VERSION 5.8 ;
BUSBITCHARS "[]" ;
DIVIDERCHAR "/" ;
UNITS
    DATABASE MICRONS 1000 ;
END UNITS

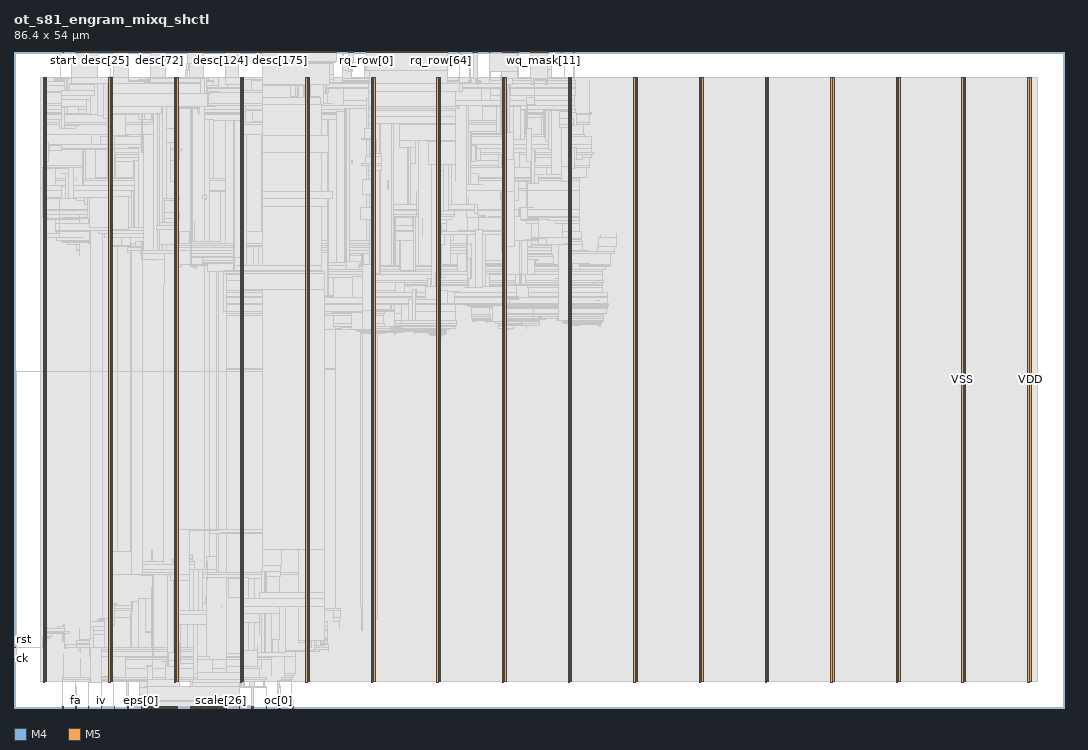
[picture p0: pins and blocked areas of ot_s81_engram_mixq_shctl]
MACRO ot_s81_engram_mixq_shctl
  FOREIGN ot_s81_engram_mixq_shctl 0 0 ;
  CLASS BLOCK ;
  SIZE 86.4 BY 54 ;
  PIN ck
    DIRECTION INPUT ;
    USE SIGNAL ;
    PORT
      LAYER M4 ;
        RECT  0 4.032 0.084 4.056 ;
    END
  END ck
  PIN copy[0]
    DIRECTION OUTPUT ;
    USE SIGNAL ;
    PORT
      LAYER M5 ;
        RECT  9.312 0 9.336 0.084 ;
    END
  END copy[0]
  PIN copy[1]
    DIRECTION OUTPUT ;
    USE SIGNAL ;
    PORT
      LAYER M5 ;
        RECT  9.408 0 9.432 0.084 ;
    END
  END copy[1]
  PIN desc[0]
    DIRECTION INPUT ;
    USE SIGNAL ;
    PORT
      LAYER M5 ;
        RECT  5.088 53.916 5.112 54 ;
    END
  END desc[0]
  PIN desc[100]
    DIRECTION INPUT ;
    USE SIGNAL ;
    PORT
      LAYER M5 ;
        RECT  14.688 53.916 14.712 54 ;
    END
  END desc[100]
  PIN desc[101]
    DIRECTION INPUT ;
    USE SIGNAL ;
    PORT
      LAYER M5 ;
        RECT  14.784 53.916 14.808 54 ;
    END
  END desc[101]
  PIN desc[102]
    DIRECTION INPUT ;
    USE SIGNAL ;
    PORT
      LAYER M5 ;
        RECT  14.88 53.916 14.904 54 ;
    END
  END desc[102]
  PIN desc[103]
    DIRECTION INPUT ;
    USE SIGNAL ;
    PORT
      LAYER M5 ;
        RECT  14.976 53.916 15 54 ;
    END
  END desc[103]
  PIN desc[104]
    DIRECTION INPUT ;
    USE SIGNAL ;
    PORT
      LAYER M5 ;
        RECT  15.072 53.916 15.096 54 ;
    END
  END desc[104]
  PIN desc[105]
    DIRECTION INPUT ;
    USE SIGNAL ;
    PORT
      LAYER M5 ;
        RECT  15.168 53.916 15.192 54 ;
    END
  END desc[105]
  PIN desc[106]
    DIRECTION INPUT ;
    USE SIGNAL ;
    PORT
      LAYER M5 ;
        RECT  15.264 53.916 15.288 54 ;
    END
  END desc[106]
  PIN desc[107]
    DIRECTION INPUT ;
    USE SIGNAL ;
    PORT
      LAYER M5 ;
        RECT  15.36 53.916 15.384 54 ;
    END
  END desc[107]
  PIN desc[108]
    DIRECTION INPUT ;
    USE SIGNAL ;
    PORT
      LAYER M5 ;
        RECT  15.456 53.916 15.48 54 ;
    END
  END desc[108]
  PIN desc[109]
    DIRECTION INPUT ;
    USE SIGNAL ;
    PORT
      LAYER M5 ;
        RECT  15.552 53.916 15.576 54 ;
    END
  END desc[109]
  PIN desc[10]
    DIRECTION INPUT ;
    USE SIGNAL ;
    PORT
      LAYER M5 ;
        RECT  6.048 53.916 6.072 54 ;
    END
  END desc[10]
  PIN desc[110]
    DIRECTION INPUT ;
    USE SIGNAL ;
    PORT
      LAYER M5 ;
        RECT  15.648 53.916 15.672 54 ;
    END
  END desc[110]
  PIN desc[111]
    DIRECTION INPUT ;
    USE SIGNAL ;
    PORT
      LAYER M5 ;
        RECT  15.744 53.916 15.768 54 ;
    END
  END desc[111]
  PIN desc[112]
    DIRECTION INPUT ;
    USE SIGNAL ;
    PORT
      LAYER M5 ;
        RECT  15.84 53.916 15.864 54 ;
    END
  END desc[112]
  PIN desc[113]
    DIRECTION INPUT ;
    USE SIGNAL ;
    PORT
      LAYER M5 ;
        RECT  15.936 53.916 15.96 54 ;
    END
  END desc[113]
  PIN desc[114]
    DIRECTION INPUT ;
    USE SIGNAL ;
    PORT
      LAYER M5 ;
        RECT  16.032 53.916 16.056 54 ;
    END
  END desc[114]
  PIN desc[115]
    DIRECTION INPUT ;
    USE SIGNAL ;
    PORT
      LAYER M5 ;
        RECT  16.128 53.916 16.152 54 ;
    END
  END desc[115]
  PIN desc[116]
    DIRECTION INPUT ;
    USE SIGNAL ;
    PORT
      LAYER M5 ;
        RECT  16.224 53.916 16.248 54 ;
    END
  END desc[116]
  PIN desc[117]
    DIRECTION INPUT ;
    USE SIGNAL ;
    PORT
      LAYER M5 ;
        RECT  16.32 53.916 16.344 54 ;
    END
  END desc[117]
  PIN desc[118]
    DIRECTION INPUT ;
    USE SIGNAL ;
    PORT
      LAYER M5 ;
        RECT  16.416 53.916 16.44 54 ;
    END
  END desc[118]
  PIN desc[119]
    DIRECTION INPUT ;
    USE SIGNAL ;
    PORT
      LAYER M5 ;
        RECT  16.512 53.916 16.536 54 ;
    END
  END desc[119]
  PIN desc[11]
    DIRECTION INPUT ;
    USE SIGNAL ;
    PORT
      LAYER M5 ;
        RECT  6.144 53.916 6.168 54 ;
    END
  END desc[11]
  PIN desc[120]
    DIRECTION INPUT ;
    USE SIGNAL ;
    PORT
      LAYER M5 ;
        RECT  16.608 53.916 16.632 54 ;
    END
  END desc[120]
  PIN desc[121]
    DIRECTION INPUT ;
    USE SIGNAL ;
    PORT
      LAYER M5 ;
        RECT  16.704 53.916 16.728 54 ;
    END
  END desc[121]
  PIN desc[122]
    DIRECTION INPUT ;
    USE SIGNAL ;
    PORT
      LAYER M5 ;
        RECT  16.8 53.916 16.824 54 ;
    END
  END desc[122]
  PIN desc[123]
    DIRECTION INPUT ;
    USE SIGNAL ;
    PORT
      LAYER M5 ;
        RECT  16.896 53.916 16.92 54 ;
    END
  END desc[123]
  PIN desc[124]
    DIRECTION INPUT ;
    USE SIGNAL ;
    PORT
      LAYER M5 ;
        RECT  16.992 53.916 17.016 54 ;
    END
  END desc[124]
  PIN desc[125]
    DIRECTION INPUT ;
    USE SIGNAL ;
    PORT
      LAYER M5 ;
        RECT  17.088 53.916 17.112 54 ;
    END
  END desc[125]
  PIN desc[126]
    DIRECTION INPUT ;
    USE SIGNAL ;
    PORT
      LAYER M5 ;
        RECT  17.184 53.916 17.208 54 ;
    END
  END desc[126]
  PIN desc[127]
    DIRECTION INPUT ;
    USE SIGNAL ;
    PORT
      LAYER M5 ;
        RECT  17.28 53.916 17.304 54 ;
    END
  END desc[127]
  PIN desc[128]
    DIRECTION INPUT ;
    USE SIGNAL ;
    PORT
      LAYER M5 ;
        RECT  17.376 53.916 17.4 54 ;
    END
  END desc[128]
  PIN desc[129]
    DIRECTION INPUT ;
    USE SIGNAL ;
    PORT
      LAYER M5 ;
        RECT  17.472 53.916 17.496 54 ;
    END
  END desc[129]
  PIN desc[12]
    DIRECTION INPUT ;
    USE SIGNAL ;
    PORT
      LAYER M5 ;
        RECT  6.24 53.916 6.264 54 ;
    END
  END desc[12]
  PIN desc[130]
    DIRECTION INPUT ;
    USE SIGNAL ;
    PORT
      LAYER M5 ;
        RECT  17.568 53.916 17.592 54 ;
    END
  END desc[130]
  PIN desc[131]
    DIRECTION INPUT ;
    USE SIGNAL ;
    PORT
      LAYER M5 ;
        RECT  17.664 53.916 17.688 54 ;
    END
  END desc[131]
  PIN desc[132]
    DIRECTION INPUT ;
    USE SIGNAL ;
    PORT
      LAYER M5 ;
        RECT  17.76 53.916 17.784 54 ;
    END
  END desc[132]
  PIN desc[133]
    DIRECTION INPUT ;
    USE SIGNAL ;
    PORT
      LAYER M5 ;
        RECT  17.856 53.916 17.88 54 ;
    END
  END desc[133]
  PIN desc[134]
    DIRECTION INPUT ;
    USE SIGNAL ;
    PORT
      LAYER M5 ;
        RECT  17.952 53.916 17.976 54 ;
    END
  END desc[134]
  PIN desc[135]
    DIRECTION INPUT ;
    USE SIGNAL ;
    PORT
      LAYER M5 ;
        RECT  18.048 53.916 18.072 54 ;
    END
  END desc[135]
  PIN desc[136]
    DIRECTION INPUT ;
    USE SIGNAL ;
    PORT
      LAYER M5 ;
        RECT  18.144 53.916 18.168 54 ;
    END
  END desc[136]
  PIN desc[137]
    DIRECTION INPUT ;
    USE SIGNAL ;
    PORT
      LAYER M5 ;
        RECT  18.24 53.916 18.264 54 ;
    END
  END desc[137]
  PIN desc[138]
    DIRECTION INPUT ;
    USE SIGNAL ;
    PORT
      LAYER M5 ;
        RECT  18.336 53.916 18.36 54 ;
    END
  END desc[138]
  PIN desc[139]
    DIRECTION INPUT ;
    USE SIGNAL ;
    PORT
      LAYER M5 ;
        RECT  18.432 53.916 18.456 54 ;
    END
  END desc[139]
  PIN desc[13]
    DIRECTION INPUT ;
    USE SIGNAL ;
    PORT
      LAYER M5 ;
        RECT  6.336 53.916 6.36 54 ;
    END
  END desc[13]
  PIN desc[140]
    DIRECTION INPUT ;
    USE SIGNAL ;
    PORT
      LAYER M5 ;
        RECT  18.528 53.916 18.552 54 ;
    END
  END desc[140]
  PIN desc[141]
    DIRECTION INPUT ;
    USE SIGNAL ;
    PORT
      LAYER M5 ;
        RECT  18.624 53.916 18.648 54 ;
    END
  END desc[141]
  PIN desc[142]
    DIRECTION INPUT ;
    USE SIGNAL ;
    PORT
      LAYER M5 ;
        RECT  18.72 53.916 18.744 54 ;
    END
  END desc[142]
  PIN desc[143]
    DIRECTION INPUT ;
    USE SIGNAL ;
    PORT
      LAYER M5 ;
        RECT  18.816 53.916 18.84 54 ;
    END
  END desc[143]
  PIN desc[144]
    DIRECTION INPUT ;
    USE SIGNAL ;
    PORT
      LAYER M5 ;
        RECT  18.912 53.916 18.936 54 ;
    END
  END desc[144]
  PIN desc[145]
    DIRECTION INPUT ;
    USE SIGNAL ;
    PORT
      LAYER M5 ;
        RECT  19.008 53.916 19.032 54 ;
    END
  END desc[145]
  PIN desc[146]
    DIRECTION INPUT ;
    USE SIGNAL ;
    PORT
      LAYER M5 ;
        RECT  19.104 53.916 19.128 54 ;
    END
  END desc[146]
  PIN desc[147]
    DIRECTION INPUT ;
    USE SIGNAL ;
    PORT
      LAYER M5 ;
        RECT  19.2 53.916 19.224 54 ;
    END
  END desc[147]
  PIN desc[148]
    DIRECTION INPUT ;
    USE SIGNAL ;
    PORT
      LAYER M5 ;
        RECT  19.296 53.916 19.32 54 ;
    END
  END desc[148]
  PIN desc[149]
    DIRECTION INPUT ;
    USE SIGNAL ;
    PORT
      LAYER M5 ;
        RECT  19.392 53.916 19.416 54 ;
    END
  END desc[149]
  PIN desc[14]
    DIRECTION INPUT ;
    USE SIGNAL ;
    PORT
      LAYER M5 ;
        RECT  6.432 53.916 6.456 54 ;
    END
  END desc[14]
  PIN desc[150]
    DIRECTION INPUT ;
    USE SIGNAL ;
    PORT
      LAYER M5 ;
        RECT  19.488 53.916 19.512 54 ;
    END
  END desc[150]
  PIN desc[151]
    DIRECTION INPUT ;
    USE SIGNAL ;
    PORT
      LAYER M5 ;
        RECT  19.584 53.916 19.608 54 ;
    END
  END desc[151]
  PIN desc[152]
    DIRECTION INPUT ;
    USE SIGNAL ;
    PORT
      LAYER M5 ;
        RECT  19.68 53.916 19.704 54 ;
    END
  END desc[152]
  PIN desc[153]
    DIRECTION INPUT ;
    USE SIGNAL ;
    PORT
      LAYER M5 ;
        RECT  19.776 53.916 19.8 54 ;
    END
  END desc[153]
  PIN desc[154]
    DIRECTION INPUT ;
    USE SIGNAL ;
    PORT
      LAYER M5 ;
        RECT  19.872 53.916 19.896 54 ;
    END
  END desc[154]
  PIN desc[155]
    DIRECTION INPUT ;
    USE SIGNAL ;
    PORT
      LAYER M5 ;
        RECT  19.968 53.916 19.992 54 ;
    END
  END desc[155]
  PIN desc[156]
    DIRECTION INPUT ;
    USE SIGNAL ;
    PORT
      LAYER M5 ;
        RECT  20.064 53.916 20.088 54 ;
    END
  END desc[156]
  PIN desc[157]
    DIRECTION INPUT ;
    USE SIGNAL ;
    PORT
      LAYER M5 ;
        RECT  20.16 53.916 20.184 54 ;
    END
  END desc[157]
  PIN desc[158]
    DIRECTION INPUT ;
    USE SIGNAL ;
    PORT
      LAYER M5 ;
        RECT  20.256 53.916 20.28 54 ;
    END
  END desc[158]
  PIN desc[159]
    DIRECTION INPUT ;
    USE SIGNAL ;
    PORT
      LAYER M5 ;
        RECT  20.352 53.916 20.376 54 ;
    END
  END desc[159]
  PIN desc[15]
    DIRECTION INPUT ;
    USE SIGNAL ;
    PORT
      LAYER M5 ;
        RECT  6.528 53.916 6.552 54 ;
    END
  END desc[15]
  PIN desc[160]
    DIRECTION INPUT ;
    USE SIGNAL ;
    PORT
      LAYER M5 ;
        RECT  20.448 53.916 20.472 54 ;
    END
  END desc[160]
  PIN desc[161]
    DIRECTION INPUT ;
    USE SIGNAL ;
    PORT
      LAYER M5 ;
        RECT  20.544 53.916 20.568 54 ;
    END
  END desc[161]
  PIN desc[162]
    DIRECTION INPUT ;
    USE SIGNAL ;
    PORT
      LAYER M5 ;
        RECT  20.64 53.916 20.664 54 ;
    END
  END desc[162]
  PIN desc[163]
    DIRECTION INPUT ;
    USE SIGNAL ;
    PORT
      LAYER M5 ;
        RECT  20.736 53.916 20.76 54 ;
    END
  END desc[163]
  PIN desc[164]
    DIRECTION INPUT ;
    USE SIGNAL ;
    PORT
      LAYER M5 ;
        RECT  20.832 53.916 20.856 54 ;
    END
  END desc[164]
  PIN desc[165]
    DIRECTION INPUT ;
    USE SIGNAL ;
    PORT
      LAYER M5 ;
        RECT  20.928 53.916 20.952 54 ;
    END
  END desc[165]
  PIN desc[166]
    DIRECTION INPUT ;
    USE SIGNAL ;
    PORT
      LAYER M5 ;
        RECT  21.024 53.916 21.048 54 ;
    END
  END desc[166]
  PIN desc[167]
    DIRECTION INPUT ;
    USE SIGNAL ;
    PORT
      LAYER M5 ;
        RECT  21.12 53.916 21.144 54 ;
    END
  END desc[167]
  PIN desc[168]
    DIRECTION INPUT ;
    USE SIGNAL ;
    PORT
      LAYER M5 ;
        RECT  21.216 53.916 21.24 54 ;
    END
  END desc[168]
  PIN desc[169]
    DIRECTION INPUT ;
    USE SIGNAL ;
    PORT
      LAYER M5 ;
        RECT  21.312 53.916 21.336 54 ;
    END
  END desc[169]
  PIN desc[16]
    DIRECTION INPUT ;
    USE SIGNAL ;
    PORT
      LAYER M5 ;
        RECT  6.624 53.916 6.648 54 ;
    END
  END desc[16]
  PIN desc[170]
    DIRECTION INPUT ;
    USE SIGNAL ;
    PORT
      LAYER M5 ;
        RECT  21.408 53.916 21.432 54 ;
    END
  END desc[170]
  PIN desc[171]
    DIRECTION INPUT ;
    USE SIGNAL ;
    PORT
      LAYER M5 ;
        RECT  21.504 53.916 21.528 54 ;
    END
  END desc[171]
  PIN desc[172]
    DIRECTION INPUT ;
    USE SIGNAL ;
    PORT
      LAYER M5 ;
        RECT  21.6 53.916 21.624 54 ;
    END
  END desc[172]
  PIN desc[173]
    DIRECTION INPUT ;
    USE SIGNAL ;
    PORT
      LAYER M5 ;
        RECT  21.696 53.916 21.72 54 ;
    END
  END desc[173]
  PIN desc[174]
    DIRECTION INPUT ;
    USE SIGNAL ;
    PORT
      LAYER M5 ;
        RECT  21.792 53.916 21.816 54 ;
    END
  END desc[174]
  PIN desc[175]
    DIRECTION INPUT ;
    USE SIGNAL ;
    PORT
      LAYER M5 ;
        RECT  21.888 53.916 21.912 54 ;
    END
  END desc[175]
  PIN desc[176]
    DIRECTION INPUT ;
    USE SIGNAL ;
    PORT
      LAYER M5 ;
        RECT  21.984 53.916 22.008 54 ;
    END
  END desc[176]
  PIN desc[177]
    DIRECTION INPUT ;
    USE SIGNAL ;
    PORT
      LAYER M5 ;
        RECT  22.08 53.916 22.104 54 ;
    END
  END desc[177]
  PIN desc[178]
    DIRECTION INPUT ;
    USE SIGNAL ;
    PORT
      LAYER M5 ;
        RECT  22.176 53.916 22.2 54 ;
    END
  END desc[178]
  PIN desc[179]
    DIRECTION INPUT ;
    USE SIGNAL ;
    PORT
      LAYER M5 ;
        RECT  22.272 53.916 22.296 54 ;
    END
  END desc[179]
  PIN desc[17]
    DIRECTION INPUT ;
    USE SIGNAL ;
    PORT
      LAYER M5 ;
        RECT  6.72 53.916 6.744 54 ;
    END
  END desc[17]
  PIN desc[180]
    DIRECTION INPUT ;
    USE SIGNAL ;
    PORT
      LAYER M5 ;
        RECT  22.368 53.916 22.392 54 ;
    END
  END desc[180]
  PIN desc[181]
    DIRECTION INPUT ;
    USE SIGNAL ;
    PORT
      LAYER M5 ;
        RECT  22.464 53.916 22.488 54 ;
    END
  END desc[181]
  PIN desc[182]
    DIRECTION INPUT ;
    USE SIGNAL ;
    PORT
      LAYER M5 ;
        RECT  22.56 53.916 22.584 54 ;
    END
  END desc[182]
  PIN desc[183]
    DIRECTION INPUT ;
    USE SIGNAL ;
    PORT
      LAYER M5 ;
        RECT  22.656 53.916 22.68 54 ;
    END
  END desc[183]
  PIN desc[184]
    DIRECTION INPUT ;
    USE SIGNAL ;
    PORT
      LAYER M5 ;
        RECT  22.752 53.916 22.776 54 ;
    END
  END desc[184]
  PIN desc[185]
    DIRECTION INPUT ;
    USE SIGNAL ;
    PORT
      LAYER M5 ;
        RECT  22.848 53.916 22.872 54 ;
    END
  END desc[185]
  PIN desc[186]
    DIRECTION INPUT ;
    USE SIGNAL ;
    PORT
      LAYER M5 ;
        RECT  22.944 53.916 22.968 54 ;
    END
  END desc[186]
  PIN desc[187]
    DIRECTION INPUT ;
    USE SIGNAL ;
    PORT
      LAYER M5 ;
        RECT  23.04 53.916 23.064 54 ;
    END
  END desc[187]
  PIN desc[188]
    DIRECTION INPUT ;
    USE SIGNAL ;
    PORT
      LAYER M5 ;
        RECT  23.136 53.916 23.16 54 ;
    END
  END desc[188]
  PIN desc[189]
    DIRECTION INPUT ;
    USE SIGNAL ;
    PORT
      LAYER M5 ;
        RECT  23.232 53.916 23.256 54 ;
    END
  END desc[189]
  PIN desc[18]
    DIRECTION INPUT ;
    USE SIGNAL ;
    PORT
      LAYER M5 ;
        RECT  6.816 53.916 6.84 54 ;
    END
  END desc[18]
  PIN desc[190]
    DIRECTION INPUT ;
    USE SIGNAL ;
    PORT
      LAYER M5 ;
        RECT  23.328 53.916 23.352 54 ;
    END
  END desc[190]
  PIN desc[191]
    DIRECTION INPUT ;
    USE SIGNAL ;
    PORT
      LAYER M5 ;
        RECT  23.424 53.916 23.448 54 ;
    END
  END desc[191]
  PIN desc[192]
    DIRECTION INPUT ;
    USE SIGNAL ;
    PORT
      LAYER M5 ;
        RECT  23.52 53.916 23.544 54 ;
    END
  END desc[192]
  PIN desc[193]
    DIRECTION INPUT ;
    USE SIGNAL ;
    PORT
      LAYER M5 ;
        RECT  23.616 53.916 23.64 54 ;
    END
  END desc[193]
  PIN desc[194]
    DIRECTION INPUT ;
    USE SIGNAL ;
    PORT
      LAYER M5 ;
        RECT  23.712 53.916 23.736 54 ;
    END
  END desc[194]
  PIN desc[195]
    DIRECTION INPUT ;
    USE SIGNAL ;
    PORT
      LAYER M5 ;
        RECT  23.808 53.916 23.832 54 ;
    END
  END desc[195]
  PIN desc[196]
    DIRECTION INPUT ;
    USE SIGNAL ;
    PORT
      LAYER M5 ;
        RECT  23.904 53.916 23.928 54 ;
    END
  END desc[196]
  PIN desc[197]
    DIRECTION INPUT ;
    USE SIGNAL ;
    PORT
      LAYER M5 ;
        RECT  24 53.916 24.024 54 ;
    END
  END desc[197]
  PIN desc[198]
    DIRECTION INPUT ;
    USE SIGNAL ;
    PORT
      LAYER M5 ;
        RECT  24.096 53.916 24.12 54 ;
    END
  END desc[198]
  PIN desc[199]
    DIRECTION INPUT ;
    USE SIGNAL ;
    PORT
      LAYER M5 ;
        RECT  24.192 53.916 24.216 54 ;
    END
  END desc[199]
  PIN desc[19]
    DIRECTION INPUT ;
    USE SIGNAL ;
    PORT
      LAYER M5 ;
        RECT  6.912 53.916 6.936 54 ;
    END
  END desc[19]
  PIN desc[1]
    DIRECTION INPUT ;
    USE SIGNAL ;
    PORT
      LAYER M5 ;
        RECT  5.184 53.916 5.208 54 ;
    END
  END desc[1]
  PIN desc[200]
    DIRECTION INPUT ;
    USE SIGNAL ;
    PORT
      LAYER M5 ;
        RECT  24.288 53.916 24.312 54 ;
    END
  END desc[200]
  PIN desc[201]
    DIRECTION INPUT ;
    USE SIGNAL ;
    PORT
      LAYER M5 ;
        RECT  24.384 53.916 24.408 54 ;
    END
  END desc[201]
  PIN desc[202]
    DIRECTION INPUT ;
    USE SIGNAL ;
    PORT
      LAYER M5 ;
        RECT  24.48 53.916 24.504 54 ;
    END
  END desc[202]
  PIN desc[203]
    DIRECTION INPUT ;
    USE SIGNAL ;
    PORT
      LAYER M5 ;
        RECT  24.576 53.916 24.6 54 ;
    END
  END desc[203]
  PIN desc[204]
    DIRECTION INPUT ;
    USE SIGNAL ;
    PORT
      LAYER M5 ;
        RECT  24.672 53.916 24.696 54 ;
    END
  END desc[204]
  PIN desc[205]
    DIRECTION INPUT ;
    USE SIGNAL ;
    PORT
      LAYER M5 ;
        RECT  24.768 53.916 24.792 54 ;
    END
  END desc[205]
  PIN desc[206]
    DIRECTION INPUT ;
    USE SIGNAL ;
    PORT
      LAYER M5 ;
        RECT  24.864 53.916 24.888 54 ;
    END
  END desc[206]
  PIN desc[207]
    DIRECTION INPUT ;
    USE SIGNAL ;
    PORT
      LAYER M5 ;
        RECT  24.96 53.916 24.984 54 ;
    END
  END desc[207]
  PIN desc[208]
    DIRECTION INPUT ;
    USE SIGNAL ;
    PORT
      LAYER M5 ;
        RECT  25.056 53.916 25.08 54 ;
    END
  END desc[208]
  PIN desc[209]
    DIRECTION INPUT ;
    USE SIGNAL ;
    PORT
      LAYER M5 ;
        RECT  25.152 53.916 25.176 54 ;
    END
  END desc[209]
  PIN desc[20]
    DIRECTION INPUT ;
    USE SIGNAL ;
    PORT
      LAYER M5 ;
        RECT  7.008 53.916 7.032 54 ;
    END
  END desc[20]
  PIN desc[210]
    DIRECTION INPUT ;
    USE SIGNAL ;
    PORT
      LAYER M5 ;
        RECT  25.248 53.916 25.272 54 ;
    END
  END desc[210]
  PIN desc[211]
    DIRECTION INPUT ;
    USE SIGNAL ;
    PORT
      LAYER M5 ;
        RECT  25.344 53.916 25.368 54 ;
    END
  END desc[211]
  PIN desc[212]
    DIRECTION INPUT ;
    USE SIGNAL ;
    PORT
      LAYER M5 ;
        RECT  25.44 53.916 25.464 54 ;
    END
  END desc[212]
  PIN desc[213]
    DIRECTION INPUT ;
    USE SIGNAL ;
    PORT
      LAYER M5 ;
        RECT  25.536 53.916 25.56 54 ;
    END
  END desc[213]
  PIN desc[214]
    DIRECTION INPUT ;
    USE SIGNAL ;
    PORT
      LAYER M5 ;
        RECT  25.632 53.916 25.656 54 ;
    END
  END desc[214]
  PIN desc[215]
    DIRECTION INPUT ;
    USE SIGNAL ;
    PORT
      LAYER M5 ;
        RECT  25.728 53.916 25.752 54 ;
    END
  END desc[215]
  PIN desc[216]
    DIRECTION INPUT ;
    USE SIGNAL ;
    PORT
      LAYER M5 ;
        RECT  25.824 53.916 25.848 54 ;
    END
  END desc[216]
  PIN desc[217]
    DIRECTION INPUT ;
    USE SIGNAL ;
    PORT
      LAYER M5 ;
        RECT  25.92 53.916 25.944 54 ;
    END
  END desc[217]
  PIN desc[218]
    DIRECTION INPUT ;
    USE SIGNAL ;
    PORT
      LAYER M5 ;
        RECT  26.016 53.916 26.04 54 ;
    END
  END desc[218]
  PIN desc[219]
    DIRECTION INPUT ;
    USE SIGNAL ;
    PORT
      LAYER M5 ;
        RECT  26.112 53.916 26.136 54 ;
    END
  END desc[219]
  PIN desc[21]
    DIRECTION INPUT ;
    USE SIGNAL ;
    PORT
      LAYER M5 ;
        RECT  7.104 53.916 7.128 54 ;
    END
  END desc[21]
  PIN desc[220]
    DIRECTION INPUT ;
    USE SIGNAL ;
    PORT
      LAYER M5 ;
        RECT  26.208 53.916 26.232 54 ;
    END
  END desc[220]
  PIN desc[221]
    DIRECTION INPUT ;
    USE SIGNAL ;
    PORT
      LAYER M5 ;
        RECT  26.304 53.916 26.328 54 ;
    END
  END desc[221]
  PIN desc[222]
    DIRECTION INPUT ;
    USE SIGNAL ;
    PORT
      LAYER M5 ;
        RECT  26.4 53.916 26.424 54 ;
    END
  END desc[222]
  PIN desc[223]
    DIRECTION INPUT ;
    USE SIGNAL ;
    PORT
      LAYER M5 ;
        RECT  26.496 53.916 26.52 54 ;
    END
  END desc[223]
  PIN desc[22]
    DIRECTION INPUT ;
    USE SIGNAL ;
    PORT
      LAYER M5 ;
        RECT  7.2 53.916 7.224 54 ;
    END
  END desc[22]
  PIN desc[23]
    DIRECTION INPUT ;
    USE SIGNAL ;
    PORT
      LAYER M5 ;
        RECT  7.296 53.916 7.32 54 ;
    END
  END desc[23]
  PIN desc[24]
    DIRECTION INPUT ;
    USE SIGNAL ;
    PORT
      LAYER M5 ;
        RECT  7.392 53.916 7.416 54 ;
    END
  END desc[24]
  PIN desc[25]
    DIRECTION INPUT ;
    USE SIGNAL ;
    PORT
      LAYER M5 ;
        RECT  7.488 53.916 7.512 54 ;
    END
  END desc[25]
  PIN desc[26]
    DIRECTION INPUT ;
    USE SIGNAL ;
    PORT
      LAYER M5 ;
        RECT  7.584 53.916 7.608 54 ;
    END
  END desc[26]
  PIN desc[27]
    DIRECTION INPUT ;
    USE SIGNAL ;
    PORT
      LAYER M5 ;
        RECT  7.68 53.916 7.704 54 ;
    END
  END desc[27]
  PIN desc[28]
    DIRECTION INPUT ;
    USE SIGNAL ;
    PORT
      LAYER M5 ;
        RECT  7.776 53.916 7.8 54 ;
    END
  END desc[28]
  PIN desc[29]
    DIRECTION INPUT ;
    USE SIGNAL ;
    PORT
      LAYER M5 ;
        RECT  7.872 53.916 7.896 54 ;
    END
  END desc[29]
  PIN desc[2]
    DIRECTION INPUT ;
    USE SIGNAL ;
    PORT
      LAYER M5 ;
        RECT  5.28 53.916 5.304 54 ;
    END
  END desc[2]
  PIN desc[30]
    DIRECTION INPUT ;
    USE SIGNAL ;
    PORT
      LAYER M5 ;
        RECT  7.968 53.916 7.992 54 ;
    END
  END desc[30]
  PIN desc[31]
    DIRECTION INPUT ;
    USE SIGNAL ;
    PORT
      LAYER M5 ;
        RECT  8.064 53.916 8.088 54 ;
    END
  END desc[31]
  PIN desc[32]
    DIRECTION INPUT ;
    USE SIGNAL ;
    PORT
      LAYER M5 ;
        RECT  8.16 53.916 8.184 54 ;
    END
  END desc[32]
  PIN desc[33]
    DIRECTION INPUT ;
    USE SIGNAL ;
    PORT
      LAYER M5 ;
        RECT  8.256 53.916 8.28 54 ;
    END
  END desc[33]
  PIN desc[34]
    DIRECTION INPUT ;
    USE SIGNAL ;
    PORT
      LAYER M5 ;
        RECT  8.352 53.916 8.376 54 ;
    END
  END desc[34]
  PIN desc[35]
    DIRECTION INPUT ;
    USE SIGNAL ;
    PORT
      LAYER M5 ;
        RECT  8.448 53.916 8.472 54 ;
    END
  END desc[35]
  PIN desc[36]
    DIRECTION INPUT ;
    USE SIGNAL ;
    PORT
      LAYER M5 ;
        RECT  8.544 53.916 8.568 54 ;
    END
  END desc[36]
  PIN desc[37]
    DIRECTION INPUT ;
    USE SIGNAL ;
    PORT
      LAYER M5 ;
        RECT  8.64 53.916 8.664 54 ;
    END
  END desc[37]
  PIN desc[38]
    DIRECTION INPUT ;
    USE SIGNAL ;
    PORT
      LAYER M5 ;
        RECT  8.736 53.916 8.76 54 ;
    END
  END desc[38]
  PIN desc[39]
    DIRECTION INPUT ;
    USE SIGNAL ;
    PORT
      LAYER M5 ;
        RECT  8.832 53.916 8.856 54 ;
    END
  END desc[39]
  PIN desc[3]
    DIRECTION INPUT ;
    USE SIGNAL ;
    PORT
      LAYER M5 ;
        RECT  5.376 53.916 5.4 54 ;
    END
  END desc[3]
  PIN desc[40]
    DIRECTION INPUT ;
    USE SIGNAL ;
    PORT
      LAYER M5 ;
        RECT  8.928 53.916 8.952 54 ;
    END
  END desc[40]
  PIN desc[41]
    DIRECTION INPUT ;
    USE SIGNAL ;
    PORT
      LAYER M5 ;
        RECT  9.024 53.916 9.048 54 ;
    END
  END desc[41]
  PIN desc[42]
    DIRECTION INPUT ;
    USE SIGNAL ;
    PORT
      LAYER M5 ;
        RECT  9.12 53.916 9.144 54 ;
    END
  END desc[42]
  PIN desc[43]
    DIRECTION INPUT ;
    USE SIGNAL ;
    PORT
      LAYER M5 ;
        RECT  9.216 53.916 9.24 54 ;
    END
  END desc[43]
  PIN desc[44]
    DIRECTION INPUT ;
    USE SIGNAL ;
    PORT
      LAYER M5 ;
        RECT  9.312 53.916 9.336 54 ;
    END
  END desc[44]
  PIN desc[45]
    DIRECTION INPUT ;
    USE SIGNAL ;
    PORT
      LAYER M5 ;
        RECT  9.408 53.916 9.432 54 ;
    END
  END desc[45]
  PIN desc[46]
    DIRECTION INPUT ;
    USE SIGNAL ;
    PORT
      LAYER M5 ;
        RECT  9.504 53.916 9.528 54 ;
    END
  END desc[46]
  PIN desc[47]
    DIRECTION INPUT ;
    USE SIGNAL ;
    PORT
      LAYER M5 ;
        RECT  9.6 53.916 9.624 54 ;
    END
  END desc[47]
  PIN desc[48]
    DIRECTION INPUT ;
    USE SIGNAL ;
    PORT
      LAYER M5 ;
        RECT  9.696 53.916 9.72 54 ;
    END
  END desc[48]
  PIN desc[49]
    DIRECTION INPUT ;
    USE SIGNAL ;
    PORT
      LAYER M5 ;
        RECT  9.792 53.916 9.816 54 ;
    END
  END desc[49]
  PIN desc[4]
    DIRECTION INPUT ;
    USE SIGNAL ;
    PORT
      LAYER M5 ;
        RECT  5.472 53.916 5.496 54 ;
    END
  END desc[4]
  PIN desc[50]
    DIRECTION INPUT ;
    USE SIGNAL ;
    PORT
      LAYER M5 ;
        RECT  9.888 53.916 9.912 54 ;
    END
  END desc[50]
  PIN desc[51]
    DIRECTION INPUT ;
    USE SIGNAL ;
    PORT
      LAYER M5 ;
        RECT  9.984 53.916 10.008 54 ;
    END
  END desc[51]
  PIN desc[52]
    DIRECTION INPUT ;
    USE SIGNAL ;
    PORT
      LAYER M5 ;
        RECT  10.08 53.916 10.104 54 ;
    END
  END desc[52]
  PIN desc[53]
    DIRECTION INPUT ;
    USE SIGNAL ;
    PORT
      LAYER M5 ;
        RECT  10.176 53.916 10.2 54 ;
    END
  END desc[53]
  PIN desc[54]
    DIRECTION INPUT ;
    USE SIGNAL ;
    PORT
      LAYER M5 ;
        RECT  10.272 53.916 10.296 54 ;
    END
  END desc[54]
  PIN desc[55]
    DIRECTION INPUT ;
    USE SIGNAL ;
    PORT
      LAYER M5 ;
        RECT  10.368 53.916 10.392 54 ;
    END
  END desc[55]
  PIN desc[56]
    DIRECTION INPUT ;
    USE SIGNAL ;
    PORT
      LAYER M5 ;
        RECT  10.464 53.916 10.488 54 ;
    END
  END desc[56]
  PIN desc[57]
    DIRECTION INPUT ;
    USE SIGNAL ;
    PORT
      LAYER M5 ;
        RECT  10.56 53.916 10.584 54 ;
    END
  END desc[57]
  PIN desc[58]
    DIRECTION INPUT ;
    USE SIGNAL ;
    PORT
      LAYER M5 ;
        RECT  10.656 53.916 10.68 54 ;
    END
  END desc[58]
  PIN desc[59]
    DIRECTION INPUT ;
    USE SIGNAL ;
    PORT
      LAYER M5 ;
        RECT  10.752 53.916 10.776 54 ;
    END
  END desc[59]
  PIN desc[5]
    DIRECTION INPUT ;
    USE SIGNAL ;
    PORT
      LAYER M5 ;
        RECT  5.568 53.916 5.592 54 ;
    END
  END desc[5]
  PIN desc[60]
    DIRECTION INPUT ;
    USE SIGNAL ;
    PORT
      LAYER M5 ;
        RECT  10.848 53.916 10.872 54 ;
    END
  END desc[60]
  PIN desc[61]
    DIRECTION INPUT ;
    USE SIGNAL ;
    PORT
      LAYER M5 ;
        RECT  10.944 53.916 10.968 54 ;
    END
  END desc[61]
  PIN desc[62]
    DIRECTION INPUT ;
    USE SIGNAL ;
    PORT
      LAYER M5 ;
        RECT  11.04 53.916 11.064 54 ;
    END
  END desc[62]
  PIN desc[63]
    DIRECTION INPUT ;
    USE SIGNAL ;
    PORT
      LAYER M5 ;
        RECT  11.136 53.916 11.16 54 ;
    END
  END desc[63]
  PIN desc[64]
    DIRECTION INPUT ;
    USE SIGNAL ;
    PORT
      LAYER M5 ;
        RECT  11.232 53.916 11.256 54 ;
    END
  END desc[64]
  PIN desc[65]
    DIRECTION INPUT ;
    USE SIGNAL ;
    PORT
      LAYER M5 ;
        RECT  11.328 53.916 11.352 54 ;
    END
  END desc[65]
  PIN desc[66]
    DIRECTION INPUT ;
    USE SIGNAL ;
    PORT
      LAYER M5 ;
        RECT  11.424 53.916 11.448 54 ;
    END
  END desc[66]
  PIN desc[67]
    DIRECTION INPUT ;
    USE SIGNAL ;
    PORT
      LAYER M5 ;
        RECT  11.52 53.916 11.544 54 ;
    END
  END desc[67]
  PIN desc[68]
    DIRECTION INPUT ;
    USE SIGNAL ;
    PORT
      LAYER M5 ;
        RECT  11.616 53.916 11.64 54 ;
    END
  END desc[68]
  PIN desc[69]
    DIRECTION INPUT ;
    USE SIGNAL ;
    PORT
      LAYER M5 ;
        RECT  11.712 53.916 11.736 54 ;
    END
  END desc[69]
  PIN desc[6]
    DIRECTION INPUT ;
    USE SIGNAL ;
    PORT
      LAYER M5 ;
        RECT  5.664 53.916 5.688 54 ;
    END
  END desc[6]
  PIN desc[70]
    DIRECTION INPUT ;
    USE SIGNAL ;
    PORT
      LAYER M5 ;
        RECT  11.808 53.916 11.832 54 ;
    END
  END desc[70]
  PIN desc[71]
    DIRECTION INPUT ;
    USE SIGNAL ;
    PORT
      LAYER M5 ;
        RECT  11.904 53.916 11.928 54 ;
    END
  END desc[71]
  PIN desc[72]
    DIRECTION INPUT ;
    USE SIGNAL ;
    PORT
      LAYER M5 ;
        RECT  12 53.916 12.024 54 ;
    END
  END desc[72]
  PIN desc[73]
    DIRECTION INPUT ;
    USE SIGNAL ;
    PORT
      LAYER M5 ;
        RECT  12.096 53.916 12.12 54 ;
    END
  END desc[73]
  PIN desc[74]
    DIRECTION INPUT ;
    USE SIGNAL ;
    PORT
      LAYER M5 ;
        RECT  12.192 53.916 12.216 54 ;
    END
  END desc[74]
  PIN desc[75]
    DIRECTION INPUT ;
    USE SIGNAL ;
    PORT
      LAYER M5 ;
        RECT  12.288 53.916 12.312 54 ;
    END
  END desc[75]
  PIN desc[76]
    DIRECTION INPUT ;
    USE SIGNAL ;
    PORT
      LAYER M5 ;
        RECT  12.384 53.916 12.408 54 ;
    END
  END desc[76]
  PIN desc[77]
    DIRECTION INPUT ;
    USE SIGNAL ;
    PORT
      LAYER M5 ;
        RECT  12.48 53.916 12.504 54 ;
    END
  END desc[77]
  PIN desc[78]
    DIRECTION INPUT ;
    USE SIGNAL ;
    PORT
      LAYER M5 ;
        RECT  12.576 53.916 12.6 54 ;
    END
  END desc[78]
  PIN desc[79]
    DIRECTION INPUT ;
    USE SIGNAL ;
    PORT
      LAYER M5 ;
        RECT  12.672 53.916 12.696 54 ;
    END
  END desc[79]
  PIN desc[7]
    DIRECTION INPUT ;
    USE SIGNAL ;
    PORT
      LAYER M5 ;
        RECT  5.76 53.916 5.784 54 ;
    END
  END desc[7]
  PIN desc[80]
    DIRECTION INPUT ;
    USE SIGNAL ;
    PORT
      LAYER M5 ;
        RECT  12.768 53.916 12.792 54 ;
    END
  END desc[80]
  PIN desc[81]
    DIRECTION INPUT ;
    USE SIGNAL ;
    PORT
      LAYER M5 ;
        RECT  12.864 53.916 12.888 54 ;
    END
  END desc[81]
  PIN desc[82]
    DIRECTION INPUT ;
    USE SIGNAL ;
    PORT
      LAYER M5 ;
        RECT  12.96 53.916 12.984 54 ;
    END
  END desc[82]
  PIN desc[83]
    DIRECTION INPUT ;
    USE SIGNAL ;
    PORT
      LAYER M5 ;
        RECT  13.056 53.916 13.08 54 ;
    END
  END desc[83]
  PIN desc[84]
    DIRECTION INPUT ;
    USE SIGNAL ;
    PORT
      LAYER M5 ;
        RECT  13.152 53.916 13.176 54 ;
    END
  END desc[84]
  PIN desc[85]
    DIRECTION INPUT ;
    USE SIGNAL ;
    PORT
      LAYER M5 ;
        RECT  13.248 53.916 13.272 54 ;
    END
  END desc[85]
  PIN desc[86]
    DIRECTION INPUT ;
    USE SIGNAL ;
    PORT
      LAYER M5 ;
        RECT  13.344 53.916 13.368 54 ;
    END
  END desc[86]
  PIN desc[87]
    DIRECTION INPUT ;
    USE SIGNAL ;
    PORT
      LAYER M5 ;
        RECT  13.44 53.916 13.464 54 ;
    END
  END desc[87]
  PIN desc[88]
    DIRECTION INPUT ;
    USE SIGNAL ;
    PORT
      LAYER M5 ;
        RECT  13.536 53.916 13.56 54 ;
    END
  END desc[88]
  PIN desc[89]
    DIRECTION INPUT ;
    USE SIGNAL ;
    PORT
      LAYER M5 ;
        RECT  13.632 53.916 13.656 54 ;
    END
  END desc[89]
  PIN desc[8]
    DIRECTION INPUT ;
    USE SIGNAL ;
    PORT
      LAYER M5 ;
        RECT  5.856 53.916 5.88 54 ;
    END
  END desc[8]
  PIN desc[90]
    DIRECTION INPUT ;
    USE SIGNAL ;
    PORT
      LAYER M5 ;
        RECT  13.728 53.916 13.752 54 ;
    END
  END desc[90]
  PIN desc[91]
    DIRECTION INPUT ;
    USE SIGNAL ;
    PORT
      LAYER M5 ;
        RECT  13.824 53.916 13.848 54 ;
    END
  END desc[91]
  PIN desc[92]
    DIRECTION INPUT ;
    USE SIGNAL ;
    PORT
      LAYER M5 ;
        RECT  13.92 53.916 13.944 54 ;
    END
  END desc[92]
  PIN desc[93]
    DIRECTION INPUT ;
    USE SIGNAL ;
    PORT
      LAYER M5 ;
        RECT  14.016 53.916 14.04 54 ;
    END
  END desc[93]
  PIN desc[94]
    DIRECTION INPUT ;
    USE SIGNAL ;
    PORT
      LAYER M5 ;
        RECT  14.112 53.916 14.136 54 ;
    END
  END desc[94]
  PIN desc[95]
    DIRECTION INPUT ;
    USE SIGNAL ;
    PORT
      LAYER M5 ;
        RECT  14.208 53.916 14.232 54 ;
    END
  END desc[95]
  PIN desc[96]
    DIRECTION INPUT ;
    USE SIGNAL ;
    PORT
      LAYER M5 ;
        RECT  14.304 53.916 14.328 54 ;
    END
  END desc[96]
  PIN desc[97]
    DIRECTION INPUT ;
    USE SIGNAL ;
    PORT
      LAYER M5 ;
        RECT  14.4 53.916 14.424 54 ;
    END
  END desc[97]
  PIN desc[98]
    DIRECTION INPUT ;
    USE SIGNAL ;
    PORT
      LAYER M5 ;
        RECT  14.496 53.916 14.52 54 ;
    END
  END desc[98]
  PIN desc[99]
    DIRECTION INPUT ;
    USE SIGNAL ;
    PORT
      LAYER M5 ;
        RECT  14.592 53.916 14.616 54 ;
    END
  END desc[99]
  PIN desc[9]
    DIRECTION INPUT ;
    USE SIGNAL ;
    PORT
      LAYER M5 ;
        RECT  5.952 53.916 5.976 54 ;
    END
  END desc[9]
  PIN done
    DIRECTION OUTPUT ;
    USE SIGNAL ;
    PORT
      LAYER M5 ;
        RECT  45.024 53.916 45.048 54 ;
    END
  END done
  PIN eps[0]
    DIRECTION OUTPUT ;
    USE SIGNAL ;
    PORT
      LAYER M5 ;
        RECT  10.464 0 10.488 0.084 ;
    END
  END eps[0]
  PIN eps[10]
    DIRECTION OUTPUT ;
    USE SIGNAL ;
    PORT
      LAYER M5 ;
        RECT  11.424 0 11.448 0.084 ;
    END
  END eps[10]
  PIN eps[11]
    DIRECTION OUTPUT ;
    USE SIGNAL ;
    PORT
      LAYER M5 ;
        RECT  11.52 0 11.544 0.084 ;
    END
  END eps[11]
  PIN eps[12]
    DIRECTION OUTPUT ;
    USE SIGNAL ;
    PORT
      LAYER M5 ;
        RECT  11.616 0 11.64 0.084 ;
    END
  END eps[12]
  PIN eps[13]
    DIRECTION OUTPUT ;
    USE SIGNAL ;
    PORT
      LAYER M5 ;
        RECT  11.712 0 11.736 0.084 ;
    END
  END eps[13]
  PIN eps[14]
    DIRECTION OUTPUT ;
    USE SIGNAL ;
    PORT
      LAYER M5 ;
        RECT  11.808 0 11.832 0.084 ;
    END
  END eps[14]
  PIN eps[15]
    DIRECTION OUTPUT ;
    USE SIGNAL ;
    PORT
      LAYER M5 ;
        RECT  11.904 0 11.928 0.084 ;
    END
  END eps[15]
  PIN eps[16]
    DIRECTION OUTPUT ;
    USE SIGNAL ;
    PORT
      LAYER M5 ;
        RECT  12 0 12.024 0.084 ;
    END
  END eps[16]
  PIN eps[17]
    DIRECTION OUTPUT ;
    USE SIGNAL ;
    PORT
      LAYER M5 ;
        RECT  12.096 0 12.12 0.084 ;
    END
  END eps[17]
  PIN eps[18]
    DIRECTION OUTPUT ;
    USE SIGNAL ;
    PORT
      LAYER M5 ;
        RECT  12.192 0 12.216 0.084 ;
    END
  END eps[18]
  PIN eps[19]
    DIRECTION OUTPUT ;
    USE SIGNAL ;
    PORT
      LAYER M5 ;
        RECT  12.288 0 12.312 0.084 ;
    END
  END eps[19]
  PIN eps[1]
    DIRECTION OUTPUT ;
    USE SIGNAL ;
    PORT
      LAYER M5 ;
        RECT  10.56 0 10.584 0.084 ;
    END
  END eps[1]
  PIN eps[20]
    DIRECTION OUTPUT ;
    USE SIGNAL ;
    PORT
      LAYER M5 ;
        RECT  12.384 0 12.408 0.084 ;
    END
  END eps[20]
  PIN eps[21]
    DIRECTION OUTPUT ;
    USE SIGNAL ;
    PORT
      LAYER M5 ;
        RECT  12.48 0 12.504 0.084 ;
    END
  END eps[21]
  PIN eps[22]
    DIRECTION OUTPUT ;
    USE SIGNAL ;
    PORT
      LAYER M5 ;
        RECT  12.576 0 12.6 0.084 ;
    END
  END eps[22]
  PIN eps[23]
    DIRECTION OUTPUT ;
    USE SIGNAL ;
    PORT
      LAYER M5 ;
        RECT  12.672 0 12.696 0.084 ;
    END
  END eps[23]
  PIN eps[24]
    DIRECTION OUTPUT ;
    USE SIGNAL ;
    PORT
      LAYER M5 ;
        RECT  12.768 0 12.792 0.084 ;
    END
  END eps[24]
  PIN eps[25]
    DIRECTION OUTPUT ;
    USE SIGNAL ;
    PORT
      LAYER M5 ;
        RECT  12.864 0 12.888 0.084 ;
    END
  END eps[25]
  PIN eps[26]
    DIRECTION OUTPUT ;
    USE SIGNAL ;
    PORT
      LAYER M5 ;
        RECT  12.96 0 12.984 0.084 ;
    END
  END eps[26]
  PIN eps[27]
    DIRECTION OUTPUT ;
    USE SIGNAL ;
    PORT
      LAYER M5 ;
        RECT  13.056 0 13.08 0.084 ;
    END
  END eps[27]
  PIN eps[28]
    DIRECTION OUTPUT ;
    USE SIGNAL ;
    PORT
      LAYER M5 ;
        RECT  13.152 0 13.176 0.084 ;
    END
  END eps[28]
  PIN eps[29]
    DIRECTION OUTPUT ;
    USE SIGNAL ;
    PORT
      LAYER M5 ;
        RECT  13.248 0 13.272 0.084 ;
    END
  END eps[29]
  PIN eps[2]
    DIRECTION OUTPUT ;
    USE SIGNAL ;
    PORT
      LAYER M5 ;
        RECT  10.656 0 10.68 0.084 ;
    END
  END eps[2]
  PIN eps[30]
    DIRECTION OUTPUT ;
    USE SIGNAL ;
    PORT
      LAYER M5 ;
        RECT  13.344 0 13.368 0.084 ;
    END
  END eps[30]
  PIN eps[31]
    DIRECTION OUTPUT ;
    USE SIGNAL ;
    PORT
      LAYER M5 ;
        RECT  13.44 0 13.464 0.084 ;
    END
  END eps[31]
  PIN eps[3]
    DIRECTION OUTPUT ;
    USE SIGNAL ;
    PORT
      LAYER M5 ;
        RECT  10.752 0 10.776 0.084 ;
    END
  END eps[3]
  PIN eps[4]
    DIRECTION OUTPUT ;
    USE SIGNAL ;
    PORT
      LAYER M5 ;
        RECT  10.848 0 10.872 0.084 ;
    END
  END eps[4]
  PIN eps[5]
    DIRECTION OUTPUT ;
    USE SIGNAL ;
    PORT
      LAYER M5 ;
        RECT  10.944 0 10.968 0.084 ;
    END
  END eps[5]
  PIN eps[6]
    DIRECTION OUTPUT ;
    USE SIGNAL ;
    PORT
      LAYER M5 ;
        RECT  11.04 0 11.064 0.084 ;
    END
  END eps[6]
  PIN eps[7]
    DIRECTION OUTPUT ;
    USE SIGNAL ;
    PORT
      LAYER M5 ;
        RECT  11.136 0 11.16 0.084 ;
    END
  END eps[7]
  PIN eps[8]
    DIRECTION OUTPUT ;
    USE SIGNAL ;
    PORT
      LAYER M5 ;
        RECT  11.232 0 11.256 0.084 ;
    END
  END eps[8]
  PIN eps[9]
    DIRECTION OUTPUT ;
    USE SIGNAL ;
    PORT
      LAYER M5 ;
        RECT  11.328 0 11.352 0.084 ;
    END
  END eps[9]
  PIN fa
    DIRECTION OUTPUT ;
    USE SIGNAL ;
    PORT
      LAYER M5 ;
        RECT  5.088 0 5.112 0.084 ;
    END
  END fa
  PIN fault
    DIRECTION OUTPUT ;
    USE SIGNAL ;
    PORT
      LAYER M5 ;
        RECT  46.08 53.916 46.104 54 ;
    END
  END fault
  PIN fr
    DIRECTION OUTPUT ;
    USE SIGNAL ;
    PORT
      LAYER M5 ;
        RECT  4.032 0 4.056 0.084 ;
    END
  END fr
  PIN gc[0]
    DIRECTION INPUT ;
    USE SIGNAL ;
    PORT
      LAYER M5 ;
        RECT  19.584 0 19.608 0.084 ;
    END
  END gc[0]
  PIN gc[1]
    DIRECTION INPUT ;
    USE SIGNAL ;
    PORT
      LAYER M5 ;
        RECT  19.68 0 19.704 0.084 ;
    END
  END gc[1]
  PIN go
    DIRECTION OUTPUT ;
    USE SIGNAL ;
    PORT
      LAYER M5 ;
        RECT  6.144 0 6.168 0.084 ;
    END
  END go
  PIN gv
    DIRECTION INPUT ;
    USE SIGNAL ;
    PORT
      LAYER M5 ;
        RECT  18.528 0 18.552 0.084 ;
    END
  END gv
  PIN iv
    DIRECTION OUTPUT ;
    USE SIGNAL ;
    PORT
      LAYER M5 ;
        RECT  7.2 0 7.224 0.084 ;
    END
  END iv
  PIN mf
    DIRECTION INPUT ;
    USE SIGNAL ;
    PORT
      LAYER M5 ;
        RECT  22.944 0 22.968 0.084 ;
    END
  END mf
  PIN oc[0]
    DIRECTION INPUT ;
    USE SIGNAL ;
    PORT
      LAYER M5 ;
        RECT  21.792 0 21.816 0.084 ;
    END
  END oc[0]
  PIN oc[1]
    DIRECTION INPUT ;
    USE SIGNAL ;
    PORT
      LAYER M5 ;
        RECT  21.888 0 21.912 0.084 ;
    END
  END oc[1]
  PIN ov
    DIRECTION INPUT ;
    USE SIGNAL ;
    PORT
      LAYER M5 ;
        RECT  20.736 0 20.76 0.084 ;
    END
  END ov
  PIN phase
    DIRECTION OUTPUT ;
    USE SIGNAL ;
    PORT
      LAYER M5 ;
        RECT  8.256 0 8.28 0.084 ;
    END
  END phase
  PIN rq_row[0]
    DIRECTION OUTPUT ;
    USE SIGNAL ;
    PORT
      LAYER M5 ;
        RECT  28.992 53.916 29.016 54 ;
    END
  END rq_row[0]
  PIN rq_row[10]
    DIRECTION OUTPUT ;
    USE SIGNAL ;
    PORT
      LAYER M5 ;
        RECT  29.952 53.916 29.976 54 ;
    END
  END rq_row[10]
  PIN rq_row[11]
    DIRECTION OUTPUT ;
    USE SIGNAL ;
    PORT
      LAYER M5 ;
        RECT  30.048 53.916 30.072 54 ;
    END
  END rq_row[11]
  PIN rq_row[12]
    DIRECTION OUTPUT ;
    USE SIGNAL ;
    PORT
      LAYER M5 ;
        RECT  30.144 53.916 30.168 54 ;
    END
  END rq_row[12]
  PIN rq_row[13]
    DIRECTION OUTPUT ;
    USE SIGNAL ;
    PORT
      LAYER M5 ;
        RECT  30.24 53.916 30.264 54 ;
    END
  END rq_row[13]
  PIN rq_row[14]
    DIRECTION OUTPUT ;
    USE SIGNAL ;
    PORT
      LAYER M5 ;
        RECT  30.336 53.916 30.36 54 ;
    END
  END rq_row[14]
  PIN rq_row[15]
    DIRECTION OUTPUT ;
    USE SIGNAL ;
    PORT
      LAYER M5 ;
        RECT  30.432 53.916 30.456 54 ;
    END
  END rq_row[15]
  PIN rq_row[16]
    DIRECTION OUTPUT ;
    USE SIGNAL ;
    PORT
      LAYER M5 ;
        RECT  30.528 53.916 30.552 54 ;
    END
  END rq_row[16]
  PIN rq_row[17]
    DIRECTION OUTPUT ;
    USE SIGNAL ;
    PORT
      LAYER M5 ;
        RECT  30.624 53.916 30.648 54 ;
    END
  END rq_row[17]
  PIN rq_row[18]
    DIRECTION OUTPUT ;
    USE SIGNAL ;
    PORT
      LAYER M5 ;
        RECT  30.72 53.916 30.744 54 ;
    END
  END rq_row[18]
  PIN rq_row[19]
    DIRECTION OUTPUT ;
    USE SIGNAL ;
    PORT
      LAYER M5 ;
        RECT  30.816 53.916 30.84 54 ;
    END
  END rq_row[19]
  PIN rq_row[1]
    DIRECTION OUTPUT ;
    USE SIGNAL ;
    PORT
      LAYER M5 ;
        RECT  29.088 53.916 29.112 54 ;
    END
  END rq_row[1]
  PIN rq_row[20]
    DIRECTION OUTPUT ;
    USE SIGNAL ;
    PORT
      LAYER M5 ;
        RECT  30.912 53.916 30.936 54 ;
    END
  END rq_row[20]
  PIN rq_row[21]
    DIRECTION OUTPUT ;
    USE SIGNAL ;
    PORT
      LAYER M5 ;
        RECT  31.008 53.916 31.032 54 ;
    END
  END rq_row[21]
  PIN rq_row[22]
    DIRECTION OUTPUT ;
    USE SIGNAL ;
    PORT
      LAYER M5 ;
        RECT  31.104 53.916 31.128 54 ;
    END
  END rq_row[22]
  PIN rq_row[23]
    DIRECTION OUTPUT ;
    USE SIGNAL ;
    PORT
      LAYER M5 ;
        RECT  31.2 53.916 31.224 54 ;
    END
  END rq_row[23]
  PIN rq_row[24]
    DIRECTION OUTPUT ;
    USE SIGNAL ;
    PORT
      LAYER M5 ;
        RECT  31.296 53.916 31.32 54 ;
    END
  END rq_row[24]
  PIN rq_row[25]
    DIRECTION OUTPUT ;
    USE SIGNAL ;
    PORT
      LAYER M5 ;
        RECT  31.392 53.916 31.416 54 ;
    END
  END rq_row[25]
  PIN rq_row[26]
    DIRECTION OUTPUT ;
    USE SIGNAL ;
    PORT
      LAYER M5 ;
        RECT  31.488 53.916 31.512 54 ;
    END
  END rq_row[26]
  PIN rq_row[27]
    DIRECTION OUTPUT ;
    USE SIGNAL ;
    PORT
      LAYER M5 ;
        RECT  31.584 53.916 31.608 54 ;
    END
  END rq_row[27]
  PIN rq_row[28]
    DIRECTION OUTPUT ;
    USE SIGNAL ;
    PORT
      LAYER M5 ;
        RECT  31.68 53.916 31.704 54 ;
    END
  END rq_row[28]
  PIN rq_row[29]
    DIRECTION OUTPUT ;
    USE SIGNAL ;
    PORT
      LAYER M5 ;
        RECT  31.776 53.916 31.8 54 ;
    END
  END rq_row[29]
  PIN rq_row[2]
    DIRECTION OUTPUT ;
    USE SIGNAL ;
    PORT
      LAYER M5 ;
        RECT  29.184 53.916 29.208 54 ;
    END
  END rq_row[2]
  PIN rq_row[30]
    DIRECTION OUTPUT ;
    USE SIGNAL ;
    PORT
      LAYER M5 ;
        RECT  31.872 53.916 31.896 54 ;
    END
  END rq_row[30]
  PIN rq_row[31]
    DIRECTION OUTPUT ;
    USE SIGNAL ;
    PORT
      LAYER M5 ;
        RECT  31.968 53.916 31.992 54 ;
    END
  END rq_row[31]
  PIN rq_row[32]
    DIRECTION OUTPUT ;
    USE SIGNAL ;
    PORT
      LAYER M5 ;
        RECT  32.064 53.916 32.088 54 ;
    END
  END rq_row[32]
  PIN rq_row[33]
    DIRECTION OUTPUT ;
    USE SIGNAL ;
    PORT
      LAYER M5 ;
        RECT  32.16 53.916 32.184 54 ;
    END
  END rq_row[33]
  PIN rq_row[34]
    DIRECTION OUTPUT ;
    USE SIGNAL ;
    PORT
      LAYER M5 ;
        RECT  32.256 53.916 32.28 54 ;
    END
  END rq_row[34]
  PIN rq_row[35]
    DIRECTION OUTPUT ;
    USE SIGNAL ;
    PORT
      LAYER M5 ;
        RECT  32.352 53.916 32.376 54 ;
    END
  END rq_row[35]
  PIN rq_row[36]
    DIRECTION OUTPUT ;
    USE SIGNAL ;
    PORT
      LAYER M5 ;
        RECT  32.448 53.916 32.472 54 ;
    END
  END rq_row[36]
  PIN rq_row[37]
    DIRECTION OUTPUT ;
    USE SIGNAL ;
    PORT
      LAYER M5 ;
        RECT  32.544 53.916 32.568 54 ;
    END
  END rq_row[37]
  PIN rq_row[38]
    DIRECTION OUTPUT ;
    USE SIGNAL ;
    PORT
      LAYER M5 ;
        RECT  32.64 53.916 32.664 54 ;
    END
  END rq_row[38]
  PIN rq_row[39]
    DIRECTION OUTPUT ;
    USE SIGNAL ;
    PORT
      LAYER M5 ;
        RECT  32.736 53.916 32.76 54 ;
    END
  END rq_row[39]
  PIN rq_row[3]
    DIRECTION OUTPUT ;
    USE SIGNAL ;
    PORT
      LAYER M5 ;
        RECT  29.28 53.916 29.304 54 ;
    END
  END rq_row[3]
  PIN rq_row[40]
    DIRECTION OUTPUT ;
    USE SIGNAL ;
    PORT
      LAYER M5 ;
        RECT  32.832 53.916 32.856 54 ;
    END
  END rq_row[40]
  PIN rq_row[41]
    DIRECTION OUTPUT ;
    USE SIGNAL ;
    PORT
      LAYER M5 ;
        RECT  32.928 53.916 32.952 54 ;
    END
  END rq_row[41]
  PIN rq_row[42]
    DIRECTION OUTPUT ;
    USE SIGNAL ;
    PORT
      LAYER M5 ;
        RECT  33.024 53.916 33.048 54 ;
    END
  END rq_row[42]
  PIN rq_row[43]
    DIRECTION OUTPUT ;
    USE SIGNAL ;
    PORT
      LAYER M5 ;
        RECT  33.12 53.916 33.144 54 ;
    END
  END rq_row[43]
  PIN rq_row[44]
    DIRECTION OUTPUT ;
    USE SIGNAL ;
    PORT
      LAYER M5 ;
        RECT  33.216 53.916 33.24 54 ;
    END
  END rq_row[44]
  PIN rq_row[45]
    DIRECTION OUTPUT ;
    USE SIGNAL ;
    PORT
      LAYER M5 ;
        RECT  33.312 53.916 33.336 54 ;
    END
  END rq_row[45]
  PIN rq_row[46]
    DIRECTION OUTPUT ;
    USE SIGNAL ;
    PORT
      LAYER M5 ;
        RECT  33.408 53.916 33.432 54 ;
    END
  END rq_row[46]
  PIN rq_row[47]
    DIRECTION OUTPUT ;
    USE SIGNAL ;
    PORT
      LAYER M5 ;
        RECT  33.504 53.916 33.528 54 ;
    END
  END rq_row[47]
  PIN rq_row[48]
    DIRECTION OUTPUT ;
    USE SIGNAL ;
    PORT
      LAYER M5 ;
        RECT  33.6 53.916 33.624 54 ;
    END
  END rq_row[48]
  PIN rq_row[49]
    DIRECTION OUTPUT ;
    USE SIGNAL ;
    PORT
      LAYER M5 ;
        RECT  33.696 53.916 33.72 54 ;
    END
  END rq_row[49]
  PIN rq_row[4]
    DIRECTION OUTPUT ;
    USE SIGNAL ;
    PORT
      LAYER M5 ;
        RECT  29.376 53.916 29.4 54 ;
    END
  END rq_row[4]
  PIN rq_row[50]
    DIRECTION OUTPUT ;
    USE SIGNAL ;
    PORT
      LAYER M5 ;
        RECT  33.792 53.916 33.816 54 ;
    END
  END rq_row[50]
  PIN rq_row[51]
    DIRECTION OUTPUT ;
    USE SIGNAL ;
    PORT
      LAYER M5 ;
        RECT  33.888 53.916 33.912 54 ;
    END
  END rq_row[51]
  PIN rq_row[52]
    DIRECTION OUTPUT ;
    USE SIGNAL ;
    PORT
      LAYER M5 ;
        RECT  33.984 53.916 34.008 54 ;
    END
  END rq_row[52]
  PIN rq_row[53]
    DIRECTION OUTPUT ;
    USE SIGNAL ;
    PORT
      LAYER M5 ;
        RECT  34.08 53.916 34.104 54 ;
    END
  END rq_row[53]
  PIN rq_row[54]
    DIRECTION OUTPUT ;
    USE SIGNAL ;
    PORT
      LAYER M5 ;
        RECT  34.176 53.916 34.2 54 ;
    END
  END rq_row[54]
  PIN rq_row[55]
    DIRECTION OUTPUT ;
    USE SIGNAL ;
    PORT
      LAYER M5 ;
        RECT  34.272 53.916 34.296 54 ;
    END
  END rq_row[55]
  PIN rq_row[56]
    DIRECTION OUTPUT ;
    USE SIGNAL ;
    PORT
      LAYER M5 ;
        RECT  34.368 53.916 34.392 54 ;
    END
  END rq_row[56]
  PIN rq_row[57]
    DIRECTION OUTPUT ;
    USE SIGNAL ;
    PORT
      LAYER M5 ;
        RECT  34.464 53.916 34.488 54 ;
    END
  END rq_row[57]
  PIN rq_row[58]
    DIRECTION OUTPUT ;
    USE SIGNAL ;
    PORT
      LAYER M5 ;
        RECT  34.56 53.916 34.584 54 ;
    END
  END rq_row[58]
  PIN rq_row[59]
    DIRECTION OUTPUT ;
    USE SIGNAL ;
    PORT
      LAYER M5 ;
        RECT  34.656 53.916 34.68 54 ;
    END
  END rq_row[59]
  PIN rq_row[5]
    DIRECTION OUTPUT ;
    USE SIGNAL ;
    PORT
      LAYER M5 ;
        RECT  29.472 53.916 29.496 54 ;
    END
  END rq_row[5]
  PIN rq_row[60]
    DIRECTION OUTPUT ;
    USE SIGNAL ;
    PORT
      LAYER M5 ;
        RECT  34.752 53.916 34.776 54 ;
    END
  END rq_row[60]
  PIN rq_row[61]
    DIRECTION OUTPUT ;
    USE SIGNAL ;
    PORT
      LAYER M5 ;
        RECT  34.848 53.916 34.872 54 ;
    END
  END rq_row[61]
  PIN rq_row[62]
    DIRECTION OUTPUT ;
    USE SIGNAL ;
    PORT
      LAYER M5 ;
        RECT  34.944 53.916 34.968 54 ;
    END
  END rq_row[62]
  PIN rq_row[63]
    DIRECTION OUTPUT ;
    USE SIGNAL ;
    PORT
      LAYER M5 ;
        RECT  35.04 53.916 35.064 54 ;
    END
  END rq_row[63]
  PIN rq_row[64]
    DIRECTION OUTPUT ;
    USE SIGNAL ;
    PORT
      LAYER M5 ;
        RECT  35.136 53.916 35.16 54 ;
    END
  END rq_row[64]
  PIN rq_row[65]
    DIRECTION OUTPUT ;
    USE SIGNAL ;
    PORT
      LAYER M5 ;
        RECT  35.232 53.916 35.256 54 ;
    END
  END rq_row[65]
  PIN rq_row[66]
    DIRECTION OUTPUT ;
    USE SIGNAL ;
    PORT
      LAYER M5 ;
        RECT  35.328 53.916 35.352 54 ;
    END
  END rq_row[66]
  PIN rq_row[67]
    DIRECTION OUTPUT ;
    USE SIGNAL ;
    PORT
      LAYER M5 ;
        RECT  35.424 53.916 35.448 54 ;
    END
  END rq_row[67]
  PIN rq_row[68]
    DIRECTION OUTPUT ;
    USE SIGNAL ;
    PORT
      LAYER M5 ;
        RECT  35.52 53.916 35.544 54 ;
    END
  END rq_row[68]
  PIN rq_row[69]
    DIRECTION OUTPUT ;
    USE SIGNAL ;
    PORT
      LAYER M5 ;
        RECT  35.616 53.916 35.64 54 ;
    END
  END rq_row[69]
  PIN rq_row[6]
    DIRECTION OUTPUT ;
    USE SIGNAL ;
    PORT
      LAYER M5 ;
        RECT  29.568 53.916 29.592 54 ;
    END
  END rq_row[6]
  PIN rq_row[7]
    DIRECTION OUTPUT ;
    USE SIGNAL ;
    PORT
      LAYER M5 ;
        RECT  29.664 53.916 29.688 54 ;
    END
  END rq_row[7]
  PIN rq_row[8]
    DIRECTION OUTPUT ;
    USE SIGNAL ;
    PORT
      LAYER M5 ;
        RECT  29.76 53.916 29.784 54 ;
    END
  END rq_row[8]
  PIN rq_row[9]
    DIRECTION OUTPUT ;
    USE SIGNAL ;
    PORT
      LAYER M5 ;
        RECT  29.856 53.916 29.88 54 ;
    END
  END rq_row[9]
  PIN rq_v[0]
    DIRECTION OUTPUT ;
    USE SIGNAL ;
    PORT
      LAYER M5 ;
        RECT  27.552 53.916 27.576 54 ;
    END
  END rq_v[0]
  PIN rq_v[1]
    DIRECTION OUTPUT ;
    USE SIGNAL ;
    PORT
      LAYER M5 ;
        RECT  27.648 53.916 27.672 54 ;
    END
  END rq_v[1]
  PIN rq_v[2]
    DIRECTION OUTPUT ;
    USE SIGNAL ;
    PORT
      LAYER M5 ;
        RECT  27.744 53.916 27.768 54 ;
    END
  END rq_v[2]
  PIN rq_v[3]
    DIRECTION OUTPUT ;
    USE SIGNAL ;
    PORT
      LAYER M5 ;
        RECT  27.84 53.916 27.864 54 ;
    END
  END rq_v[3]
  PIN rq_v[4]
    DIRECTION OUTPUT ;
    USE SIGNAL ;
    PORT
      LAYER M5 ;
        RECT  27.936 53.916 27.96 54 ;
    END
  END rq_v[4]
  PIN rs_v[0]
    DIRECTION INPUT ;
    USE SIGNAL ;
    PORT
      LAYER M5 ;
        RECT  37.728 53.916 37.752 54 ;
    END
  END rs_v[0]
  PIN rs_v[1]
    DIRECTION INPUT ;
    USE SIGNAL ;
    PORT
      LAYER M5 ;
        RECT  37.824 53.916 37.848 54 ;
    END
  END rs_v[1]
  PIN rs_v[2]
    DIRECTION INPUT ;
    USE SIGNAL ;
    PORT
      LAYER M5 ;
        RECT  37.92 53.916 37.944 54 ;
    END
  END rs_v[2]
  PIN rs_v[3]
    DIRECTION INPUT ;
    USE SIGNAL ;
    PORT
      LAYER M5 ;
        RECT  38.016 53.916 38.04 54 ;
    END
  END rs_v[3]
  PIN rs_v[4]
    DIRECTION INPUT ;
    USE SIGNAL ;
    PORT
      LAYER M5 ;
        RECT  38.112 53.916 38.136 54 ;
    END
  END rs_v[4]
  PIN rst
    DIRECTION INPUT ;
    USE SIGNAL ;
    PORT
      LAYER M4 ;
        RECT  0 4.992 0.084 5.016 ;
    END
  END rst
  PIN scale[0]
    DIRECTION OUTPUT ;
    USE SIGNAL ;
    PORT
      LAYER M5 ;
        RECT  14.496 0 14.52 0.084 ;
    END
  END scale[0]
  PIN scale[10]
    DIRECTION OUTPUT ;
    USE SIGNAL ;
    PORT
      LAYER M5 ;
        RECT  15.456 0 15.48 0.084 ;
    END
  END scale[10]
  PIN scale[11]
    DIRECTION OUTPUT ;
    USE SIGNAL ;
    PORT
      LAYER M5 ;
        RECT  15.552 0 15.576 0.084 ;
    END
  END scale[11]
  PIN scale[12]
    DIRECTION OUTPUT ;
    USE SIGNAL ;
    PORT
      LAYER M5 ;
        RECT  15.648 0 15.672 0.084 ;
    END
  END scale[12]
  PIN scale[13]
    DIRECTION OUTPUT ;
    USE SIGNAL ;
    PORT
      LAYER M5 ;
        RECT  15.744 0 15.768 0.084 ;
    END
  END scale[13]
  PIN scale[14]
    DIRECTION OUTPUT ;
    USE SIGNAL ;
    PORT
      LAYER M5 ;
        RECT  15.84 0 15.864 0.084 ;
    END
  END scale[14]
  PIN scale[15]
    DIRECTION OUTPUT ;
    USE SIGNAL ;
    PORT
      LAYER M5 ;
        RECT  15.936 0 15.96 0.084 ;
    END
  END scale[15]
  PIN scale[16]
    DIRECTION OUTPUT ;
    USE SIGNAL ;
    PORT
      LAYER M5 ;
        RECT  16.032 0 16.056 0.084 ;
    END
  END scale[16]
  PIN scale[17]
    DIRECTION OUTPUT ;
    USE SIGNAL ;
    PORT
      LAYER M5 ;
        RECT  16.128 0 16.152 0.084 ;
    END
  END scale[17]
  PIN scale[18]
    DIRECTION OUTPUT ;
    USE SIGNAL ;
    PORT
      LAYER M5 ;
        RECT  16.224 0 16.248 0.084 ;
    END
  END scale[18]
  PIN scale[19]
    DIRECTION OUTPUT ;
    USE SIGNAL ;
    PORT
      LAYER M5 ;
        RECT  16.32 0 16.344 0.084 ;
    END
  END scale[19]
  PIN scale[1]
    DIRECTION OUTPUT ;
    USE SIGNAL ;
    PORT
      LAYER M5 ;
        RECT  14.592 0 14.616 0.084 ;
    END
  END scale[1]
  PIN scale[20]
    DIRECTION OUTPUT ;
    USE SIGNAL ;
    PORT
      LAYER M5 ;
        RECT  16.416 0 16.44 0.084 ;
    END
  END scale[20]
  PIN scale[21]
    DIRECTION OUTPUT ;
    USE SIGNAL ;
    PORT
      LAYER M5 ;
        RECT  16.512 0 16.536 0.084 ;
    END
  END scale[21]
  PIN scale[22]
    DIRECTION OUTPUT ;
    USE SIGNAL ;
    PORT
      LAYER M5 ;
        RECT  16.608 0 16.632 0.084 ;
    END
  END scale[22]
  PIN scale[23]
    DIRECTION OUTPUT ;
    USE SIGNAL ;
    PORT
      LAYER M5 ;
        RECT  16.704 0 16.728 0.084 ;
    END
  END scale[23]
  PIN scale[24]
    DIRECTION OUTPUT ;
    USE SIGNAL ;
    PORT
      LAYER M5 ;
        RECT  16.8 0 16.824 0.084 ;
    END
  END scale[24]
  PIN scale[25]
    DIRECTION OUTPUT ;
    USE SIGNAL ;
    PORT
      LAYER M5 ;
        RECT  16.896 0 16.92 0.084 ;
    END
  END scale[25]
  PIN scale[26]
    DIRECTION OUTPUT ;
    USE SIGNAL ;
    PORT
      LAYER M5 ;
        RECT  16.992 0 17.016 0.084 ;
    END
  END scale[26]
  PIN scale[27]
    DIRECTION OUTPUT ;
    USE SIGNAL ;
    PORT
      LAYER M5 ;
        RECT  17.088 0 17.112 0.084 ;
    END
  END scale[27]
  PIN scale[28]
    DIRECTION OUTPUT ;
    USE SIGNAL ;
    PORT
      LAYER M5 ;
        RECT  17.184 0 17.208 0.084 ;
    END
  END scale[28]
  PIN scale[29]
    DIRECTION OUTPUT ;
    USE SIGNAL ;
    PORT
      LAYER M5 ;
        RECT  17.28 0 17.304 0.084 ;
    END
  END scale[29]
  PIN scale[2]
    DIRECTION OUTPUT ;
    USE SIGNAL ;
    PORT
      LAYER M5 ;
        RECT  14.688 0 14.712 0.084 ;
    END
  END scale[2]
  PIN scale[30]
    DIRECTION OUTPUT ;
    USE SIGNAL ;
    PORT
      LAYER M5 ;
        RECT  17.376 0 17.4 0.084 ;
    END
  END scale[30]
  PIN scale[31]
    DIRECTION OUTPUT ;
    USE SIGNAL ;
    PORT
      LAYER M5 ;
        RECT  17.472 0 17.496 0.084 ;
    END
  END scale[31]
  PIN scale[3]
    DIRECTION OUTPUT ;
    USE SIGNAL ;
    PORT
      LAYER M5 ;
        RECT  14.784 0 14.808 0.084 ;
    END
  END scale[3]
  PIN scale[4]
    DIRECTION OUTPUT ;
    USE SIGNAL ;
    PORT
      LAYER M5 ;
        RECT  14.88 0 14.904 0.084 ;
    END
  END scale[4]
  PIN scale[5]
    DIRECTION OUTPUT ;
    USE SIGNAL ;
    PORT
      LAYER M5 ;
        RECT  14.976 0 15 0.084 ;
    END
  END scale[5]
  PIN scale[6]
    DIRECTION OUTPUT ;
    USE SIGNAL ;
    PORT
      LAYER M5 ;
        RECT  15.072 0 15.096 0.084 ;
    END
  END scale[6]
  PIN scale[7]
    DIRECTION OUTPUT ;
    USE SIGNAL ;
    PORT
      LAYER M5 ;
        RECT  15.168 0 15.192 0.084 ;
    END
  END scale[7]
  PIN scale[8]
    DIRECTION OUTPUT ;
    USE SIGNAL ;
    PORT
      LAYER M5 ;
        RECT  15.264 0 15.288 0.084 ;
    END
  END scale[8]
  PIN scale[9]
    DIRECTION OUTPUT ;
    USE SIGNAL ;
    PORT
      LAYER M5 ;
        RECT  15.36 0 15.384 0.084 ;
    END
  END scale[9]
  PIN start
    DIRECTION INPUT ;
    USE SIGNAL ;
    PORT
      LAYER M5 ;
        RECT  4.032 53.916 4.056 54 ;
    END
  END start
  PIN vtag
    DIRECTION OUTPUT ;
    USE SIGNAL ;
    PORT
      LAYER M5 ;
        RECT  36.672 53.916 36.696 54 ;
    END
  END vtag
  PIN wq_mask[0]
    DIRECTION OUTPUT ;
    USE SIGNAL ;
    PORT
      LAYER M5 ;
        RECT  42.528 53.916 42.552 54 ;
    END
  END wq_mask[0]
  PIN wq_mask[10]
    DIRECTION OUTPUT ;
    USE SIGNAL ;
    PORT
      LAYER M5 ;
        RECT  43.488 53.916 43.512 54 ;
    END
  END wq_mask[10]
  PIN wq_mask[11]
    DIRECTION OUTPUT ;
    USE SIGNAL ;
    PORT
      LAYER M5 ;
        RECT  43.584 53.916 43.608 54 ;
    END
  END wq_mask[11]
  PIN wq_mask[12]
    DIRECTION OUTPUT ;
    USE SIGNAL ;
    PORT
      LAYER M5 ;
        RECT  43.68 53.916 43.704 54 ;
    END
  END wq_mask[12]
  PIN wq_mask[13]
    DIRECTION OUTPUT ;
    USE SIGNAL ;
    PORT
      LAYER M5 ;
        RECT  43.776 53.916 43.8 54 ;
    END
  END wq_mask[13]
  PIN wq_mask[14]
    DIRECTION OUTPUT ;
    USE SIGNAL ;
    PORT
      LAYER M5 ;
        RECT  43.872 53.916 43.896 54 ;
    END
  END wq_mask[14]
  PIN wq_mask[15]
    DIRECTION OUTPUT ;
    USE SIGNAL ;
    PORT
      LAYER M5 ;
        RECT  43.968 53.916 43.992 54 ;
    END
  END wq_mask[15]
  PIN wq_mask[1]
    DIRECTION OUTPUT ;
    USE SIGNAL ;
    PORT
      LAYER M5 ;
        RECT  42.624 53.916 42.648 54 ;
    END
  END wq_mask[1]
  PIN wq_mask[2]
    DIRECTION OUTPUT ;
    USE SIGNAL ;
    PORT
      LAYER M5 ;
        RECT  42.72 53.916 42.744 54 ;
    END
  END wq_mask[2]
  PIN wq_mask[3]
    DIRECTION OUTPUT ;
    USE SIGNAL ;
    PORT
      LAYER M5 ;
        RECT  42.816 53.916 42.84 54 ;
    END
  END wq_mask[3]
  PIN wq_mask[4]
    DIRECTION OUTPUT ;
    USE SIGNAL ;
    PORT
      LAYER M5 ;
        RECT  42.912 53.916 42.936 54 ;
    END
  END wq_mask[4]
  PIN wq_mask[5]
    DIRECTION OUTPUT ;
    USE SIGNAL ;
    PORT
      LAYER M5 ;
        RECT  43.008 53.916 43.032 54 ;
    END
  END wq_mask[5]
  PIN wq_mask[6]
    DIRECTION OUTPUT ;
    USE SIGNAL ;
    PORT
      LAYER M5 ;
        RECT  43.104 53.916 43.128 54 ;
    END
  END wq_mask[6]
  PIN wq_mask[7]
    DIRECTION OUTPUT ;
    USE SIGNAL ;
    PORT
      LAYER M5 ;
        RECT  43.2 53.916 43.224 54 ;
    END
  END wq_mask[7]
  PIN wq_mask[8]
    DIRECTION OUTPUT ;
    USE SIGNAL ;
    PORT
      LAYER M5 ;
        RECT  43.296 53.916 43.32 54 ;
    END
  END wq_mask[8]
  PIN wq_mask[9]
    DIRECTION OUTPUT ;
    USE SIGNAL ;
    PORT
      LAYER M5 ;
        RECT  43.392 53.916 43.416 54 ;
    END
  END wq_mask[9]
  PIN wq_row[0]
    DIRECTION OUTPUT ;
    USE SIGNAL ;
    PORT
      LAYER M5 ;
        RECT  40.224 53.916 40.248 54 ;
    END
  END wq_row[0]
  PIN wq_row[10]
    DIRECTION OUTPUT ;
    USE SIGNAL ;
    PORT
      LAYER M5 ;
        RECT  41.184 53.916 41.208 54 ;
    END
  END wq_row[10]
  PIN wq_row[11]
    DIRECTION OUTPUT ;
    USE SIGNAL ;
    PORT
      LAYER M5 ;
        RECT  41.28 53.916 41.304 54 ;
    END
  END wq_row[11]
  PIN wq_row[12]
    DIRECTION OUTPUT ;
    USE SIGNAL ;
    PORT
      LAYER M5 ;
        RECT  41.376 53.916 41.4 54 ;
    END
  END wq_row[12]
  PIN wq_row[13]
    DIRECTION OUTPUT ;
    USE SIGNAL ;
    PORT
      LAYER M5 ;
        RECT  41.472 53.916 41.496 54 ;
    END
  END wq_row[13]
  PIN wq_row[1]
    DIRECTION OUTPUT ;
    USE SIGNAL ;
    PORT
      LAYER M5 ;
        RECT  40.32 53.916 40.344 54 ;
    END
  END wq_row[1]
  PIN wq_row[2]
    DIRECTION OUTPUT ;
    USE SIGNAL ;
    PORT
      LAYER M5 ;
        RECT  40.416 53.916 40.44 54 ;
    END
  END wq_row[2]
  PIN wq_row[3]
    DIRECTION OUTPUT ;
    USE SIGNAL ;
    PORT
      LAYER M5 ;
        RECT  40.512 53.916 40.536 54 ;
    END
  END wq_row[3]
  PIN wq_row[4]
    DIRECTION OUTPUT ;
    USE SIGNAL ;
    PORT
      LAYER M5 ;
        RECT  40.608 53.916 40.632 54 ;
    END
  END wq_row[4]
  PIN wq_row[5]
    DIRECTION OUTPUT ;
    USE SIGNAL ;
    PORT
      LAYER M5 ;
        RECT  40.704 53.916 40.728 54 ;
    END
  END wq_row[5]
  PIN wq_row[6]
    DIRECTION OUTPUT ;
    USE SIGNAL ;
    PORT
      LAYER M5 ;
        RECT  40.8 53.916 40.824 54 ;
    END
  END wq_row[6]
  PIN wq_row[7]
    DIRECTION OUTPUT ;
    USE SIGNAL ;
    PORT
      LAYER M5 ;
        RECT  40.896 53.916 40.92 54 ;
    END
  END wq_row[7]
  PIN wq_row[8]
    DIRECTION OUTPUT ;
    USE SIGNAL ;
    PORT
      LAYER M5 ;
        RECT  40.992 53.916 41.016 54 ;
    END
  END wq_row[8]
  PIN wq_row[9]
    DIRECTION OUTPUT ;
    USE SIGNAL ;
    PORT
      LAYER M5 ;
        RECT  41.088 53.916 41.112 54 ;
    END
  END wq_row[9]
  PIN wq_v
    DIRECTION OUTPUT ;
    USE SIGNAL ;
    PORT
      LAYER M5 ;
        RECT  39.168 53.916 39.192 54 ;
    END
  END wq_v
  PIN VDD
    DIRECTION INOUT ;
    USE POWER ;
    PORT
      LAYER M5 ;
        RECT  83.592 2.151 83.712 51.849 ;
        RECT  78.192 2.151 78.312 51.849 ;
        RECT  72.792 2.151 72.912 51.849 ;
        RECT  67.392 2.151 67.512 51.849 ;
        RECT  61.992 2.151 62.112 51.849 ;
        RECT  56.592 2.151 56.712 51.849 ;
        RECT  51.192 2.151 51.312 51.849 ;
        RECT  45.792 2.151 45.912 51.849 ;
        RECT  40.392 2.151 40.512 51.849 ;
        RECT  34.992 2.151 35.112 51.849 ;
        RECT  29.592 2.151 29.712 51.849 ;
        RECT  24.192 2.151 24.312 51.849 ;
        RECT  18.792 2.151 18.912 51.849 ;
        RECT  13.392 2.151 13.512 51.849 ;
        RECT  7.992 2.151 8.112 51.849 ;
        RECT  2.592 2.151 2.712 51.849 ;
    END
  END VDD
  PIN VSS
    DIRECTION INOUT ;
    USE GROUND ;
    PORT
      LAYER M5 ;
        RECT  83.4 2.137 83.52 51.863 ;
        RECT  78 2.137 78.12 51.863 ;
        RECT  72.6 2.137 72.72 51.863 ;
        RECT  67.2 2.137 67.32 51.863 ;
        RECT  61.8 2.137 61.92 51.863 ;
        RECT  56.4 2.137 56.52 51.863 ;
        RECT  51 2.137 51.12 51.863 ;
        RECT  45.6 2.137 45.72 51.863 ;
        RECT  40.2 2.137 40.32 51.863 ;
        RECT  34.8 2.137 34.92 51.863 ;
        RECT  29.4 2.137 29.52 51.863 ;
        RECT  24 2.137 24.12 51.863 ;
        RECT  18.6 2.137 18.72 51.863 ;
        RECT  13.2 2.137 13.32 51.863 ;
        RECT  7.8 2.137 7.92 51.863 ;
        RECT  2.4 2.137 2.52 51.863 ;
    END
  END VSS
  OBS
    LAYER RVTN ;
     RECT  2.16 2.16 84.24 2.295 ;
     RECT  2.16 2.565 84.24 2.835 ;
     RECT  2.16 3.105 84.24 3.375 ;
     RECT  2.16 3.645 84.24 3.915 ;
     RECT  2.16 4.185 84.24 4.455 ;
     RECT  2.16 4.725 84.24 4.995 ;
     RECT  2.16 5.265 84.24 5.535 ;
     RECT  2.16 5.805 84.24 6.075 ;
     RECT  2.16 6.345 84.24 6.615 ;
     RECT  2.16 6.885 84.24 7.155 ;
     RECT  2.16 7.425 84.24 7.695 ;
     RECT  2.16 7.965 84.24 8.235 ;
     RECT  2.16 8.505 84.24 8.775 ;
     RECT  2.16 9.045 84.24 9.315 ;
     RECT  2.16 9.585 84.24 9.855 ;
     RECT  2.16 10.125 84.24 10.395 ;
     RECT  2.16 10.665 84.24 10.935 ;
     RECT  2.16 11.205 84.24 11.475 ;
     RECT  2.16 11.745 84.24 12.015 ;
     RECT  2.16 12.285 84.24 12.555 ;
     RECT  2.16 12.825 84.24 13.095 ;
     RECT  2.16 13.365 84.24 13.635 ;
     RECT  2.16 13.905 84.24 14.175 ;
     RECT  2.16 14.445 84.24 14.715 ;
     RECT  2.16 14.985 84.24 15.255 ;
     RECT  2.16 15.525 84.24 15.795 ;
     RECT  2.16 16.065 84.24 16.335 ;
     RECT  2.16 16.605 84.24 16.875 ;
     RECT  2.16 17.145 84.24 17.415 ;
     RECT  2.16 17.685 84.24 17.955 ;
     RECT  2.16 18.225 84.24 18.495 ;
     RECT  2.16 18.765 84.24 19.035 ;
     RECT  2.16 19.305 84.24 19.575 ;
     RECT  2.16 19.845 84.24 20.115 ;
     RECT  2.16 20.385 84.24 20.655 ;
     RECT  2.16 20.925 84.24 21.195 ;
     RECT  2.16 21.465 84.24 21.735 ;
     RECT  2.16 22.005 84.24 22.275 ;
     RECT  2.16 22.545 84.24 22.815 ;
     RECT  2.16 23.085 84.24 23.355 ;
     RECT  2.16 23.625 84.24 23.895 ;
     RECT  2.16 24.165 84.24 24.435 ;
     RECT  2.16 24.705 84.24 24.975 ;
     RECT  2.16 25.245 84.24 25.515 ;
     RECT  2.16 25.785 84.24 26.055 ;
     RECT  2.16 26.325 84.24 26.595 ;
     RECT  2.16 26.865 84.24 27.135 ;
     RECT  2.16 27.405 84.24 27.675 ;
     RECT  2.16 27.945 84.24 28.215 ;
     RECT  2.16 28.485 84.24 28.755 ;
     RECT  2.16 29.025 84.24 29.295 ;
     RECT  2.16 29.565 84.24 29.835 ;
     RECT  2.16 30.105 84.24 30.375 ;
     RECT  2.16 30.645 84.24 30.915 ;
     RECT  2.16 31.185 84.24 31.455 ;
     RECT  2.16 31.725 84.24 31.995 ;
     RECT  2.16 32.265 84.24 32.535 ;
     RECT  2.16 32.805 84.24 33.075 ;
     RECT  2.16 33.345 84.24 33.615 ;
     RECT  2.16 33.885 84.24 34.155 ;
     RECT  2.16 34.425 84.24 34.695 ;
     RECT  2.16 34.965 84.24 35.235 ;
     RECT  2.16 35.505 84.24 35.775 ;
     RECT  2.16 36.045 84.24 36.315 ;
     RECT  2.16 36.585 84.24 36.855 ;
     RECT  2.16 37.125 84.24 37.395 ;
     RECT  2.16 37.665 84.24 37.935 ;
     RECT  2.16 38.205 84.24 38.475 ;
     RECT  2.16 38.745 84.24 39.015 ;
     RECT  2.16 39.285 84.24 39.555 ;
     RECT  2.16 39.825 84.24 40.095 ;
     RECT  2.16 40.365 84.24 40.635 ;
     RECT  2.16 40.905 84.24 41.175 ;
     RECT  2.16 41.445 84.24 41.715 ;
     RECT  2.16 41.985 84.24 42.255 ;
     RECT  2.16 42.525 84.24 42.795 ;
     RECT  2.16 43.065 84.24 43.335 ;
     RECT  2.16 43.605 84.24 43.875 ;
     RECT  2.16 44.145 84.24 44.415 ;
     RECT  2.16 44.685 84.24 44.955 ;
     RECT  2.16 45.225 84.24 45.495 ;
     RECT  2.16 45.765 84.24 46.035 ;
     RECT  2.16 46.305 84.24 46.575 ;
     RECT  2.16 46.845 84.24 47.115 ;
     RECT  2.16 47.385 84.24 47.655 ;
     RECT  2.16 47.925 84.24 48.195 ;
     RECT  2.16 48.465 84.24 48.735 ;
     RECT  2.16 49.005 84.24 49.275 ;
     RECT  2.16 49.545 84.24 49.815 ;
     RECT  2.16 50.085 84.24 50.355 ;
     RECT  2.16 50.625 84.24 50.895 ;
     RECT  2.16 51.165 84.24 51.435 ;
     RECT  2.16 51.705 84.24 51.84 ;
    LAYER RVTP ;
     RECT  2.16 2.295 84.24 2.565 ;
     RECT  2.16 2.835 84.24 3.105 ;
     RECT  2.16 3.375 84.24 3.645 ;
     RECT  2.16 3.915 84.24 4.185 ;
     RECT  2.16 4.455 84.24 4.725 ;
     RECT  2.16 4.995 84.24 5.265 ;
     RECT  2.16 5.535 84.24 5.805 ;
     RECT  2.16 6.075 84.24 6.345 ;
     RECT  2.16 6.615 84.24 6.885 ;
     RECT  2.16 7.155 84.24 7.425 ;
     RECT  2.16 7.695 84.24 7.965 ;
     RECT  2.16 8.235 84.24 8.505 ;
     RECT  2.16 8.775 84.24 9.045 ;
     RECT  2.16 9.315 84.24 9.585 ;
     RECT  2.16 9.855 84.24 10.125 ;
     RECT  2.16 10.395 84.24 10.665 ;
     RECT  2.16 10.935 84.24 11.205 ;
     RECT  2.16 11.475 84.24 11.745 ;
     RECT  2.16 12.015 84.24 12.285 ;
     RECT  2.16 12.555 84.24 12.825 ;
     RECT  2.16 13.095 84.24 13.365 ;
     RECT  2.16 13.635 84.24 13.905 ;
     RECT  2.16 14.175 84.24 14.445 ;
     RECT  2.16 14.715 84.24 14.985 ;
     RECT  2.16 15.255 84.24 15.525 ;
     RECT  2.16 15.795 84.24 16.065 ;
     RECT  2.16 16.335 84.24 16.605 ;
     RECT  2.16 16.875 84.24 17.145 ;
     RECT  2.16 17.415 84.24 17.685 ;
     RECT  2.16 17.955 84.24 18.225 ;
     RECT  2.16 18.495 84.24 18.765 ;
     RECT  2.16 19.035 84.24 19.305 ;
     RECT  2.16 19.575 84.24 19.845 ;
     RECT  2.16 20.115 84.24 20.385 ;
     RECT  2.16 20.655 84.24 20.925 ;
     RECT  2.16 21.195 84.24 21.465 ;
     RECT  2.16 21.735 84.24 22.005 ;
     RECT  2.16 22.275 84.24 22.545 ;
     RECT  2.16 22.815 84.24 23.085 ;
     RECT  2.16 23.355 84.24 23.625 ;
     RECT  2.16 23.895 84.24 24.165 ;
     RECT  2.16 24.435 84.24 24.705 ;
     RECT  2.16 24.975 84.24 25.245 ;
     RECT  2.16 25.515 84.24 25.785 ;
     RECT  2.16 26.055 84.24 26.325 ;
     RECT  2.16 26.595 84.24 26.865 ;
     RECT  2.16 27.135 84.24 27.405 ;
     RECT  2.16 27.675 84.24 27.945 ;
     RECT  2.16 28.215 84.24 28.485 ;
     RECT  2.16 28.755 84.24 29.025 ;
     RECT  2.16 29.295 84.24 29.565 ;
     RECT  2.16 29.835 84.24 30.105 ;
     RECT  2.16 30.375 84.24 30.645 ;
     RECT  2.16 30.915 84.24 31.185 ;
     RECT  2.16 31.455 84.24 31.725 ;
     RECT  2.16 31.995 84.24 32.265 ;
     RECT  2.16 32.535 84.24 32.805 ;
     RECT  2.16 33.075 84.24 33.345 ;
     RECT  2.16 33.615 84.24 33.885 ;
     RECT  2.16 34.155 84.24 34.425 ;
     RECT  2.16 34.695 84.24 34.965 ;
     RECT  2.16 35.235 84.24 35.505 ;
     RECT  2.16 35.775 84.24 36.045 ;
     RECT  2.16 36.315 84.24 36.585 ;
     RECT  2.16 36.855 84.24 37.125 ;
     RECT  2.16 37.395 84.24 37.665 ;
     RECT  2.16 37.935 84.24 38.205 ;
     RECT  2.16 38.475 84.24 38.745 ;
     RECT  2.16 39.015 84.24 39.285 ;
     RECT  2.16 39.555 84.24 39.825 ;
     RECT  2.16 40.095 84.24 40.365 ;
     RECT  2.16 40.635 84.24 40.905 ;
     RECT  2.16 41.175 84.24 41.445 ;
     RECT  2.16 41.715 84.24 41.985 ;
     RECT  2.16 42.255 84.24 42.525 ;
     RECT  2.16 42.795 84.24 43.065 ;
     RECT  2.16 43.335 84.24 43.605 ;
     RECT  2.16 43.875 84.24 44.145 ;
     RECT  2.16 44.415 84.24 44.685 ;
     RECT  2.16 44.955 84.24 45.225 ;
     RECT  2.16 45.495 84.24 45.765 ;
     RECT  2.16 46.035 84.24 46.305 ;
     RECT  2.16 46.575 84.24 46.845 ;
     RECT  2.16 47.115 84.24 47.385 ;
     RECT  2.16 47.655 84.24 47.925 ;
     RECT  2.16 48.195 84.24 48.465 ;
     RECT  2.16 48.735 84.24 49.005 ;
     RECT  2.16 49.275 84.24 49.545 ;
     RECT  2.16 49.815 84.24 50.085 ;
     RECT  2.16 50.355 84.24 50.625 ;
     RECT  2.16 50.895 84.24 51.165 ;
     RECT  2.16 51.435 84.24 51.705 ;
    LAYER M1 ;
     RECT  2.16 2.151 84.24 51.849 ;
    LAYER M2 ;
     RECT  2.16 2.151 6.295 51.849 ;
     RECT  6.295 2.106 7.259 51.849 ;
     RECT  14.539 1.152 14.639 1.17 ;
     RECT  15.439 1.152 15.575 1.17 ;
     RECT  7.259 2.151 15.691 51.849 ;
     RECT  15.691 2.106 16.835 51.849 ;
     RECT  16.483 0.531 18.247 0.549 ;
     RECT  18.247 0.531 18.311 1.17 ;
     RECT  18.311 1.152 18.383 1.17 ;
     RECT  20.731 52.992 20.831 53.01 ;
     RECT  16.835 2.151 84.24 51.849 ;
    LAYER M3 ;
     RECT  9.288 0.091 9.306 0.139 ;
     RECT  10.44 0.091 11.466 0.139 ;
     RECT  18.252 0.091 18.27 0.52 ;
     RECT  14.616 0.091 14.814 0.523 ;
     RECT  15.552 0.139 15.57 0.523 ;
     RECT  16.488 0.52 16.506 0.557 ;
     RECT  12.24 0.091 12.258 0.571 ;
     RECT  14.616 0.523 15.57 1.099 ;
     RECT  10.332 0.139 11.466 1.147 ;
     RECT  12.24 0.571 12.438 1.147 ;
     RECT  14.616 1.099 16.038 1.147 ;
     RECT  18.252 0.52 18.306 1.147 ;
     RECT  18.252 1.147 18.378 1.175 ;
     RECT  10.332 1.147 13.374 1.723 ;
     RECT  14.544 1.147 16.038 1.723 ;
     RECT  17.496 1.147 17.514 1.723 ;
     RECT  18.36 1.175 18.378 1.723 ;
     RECT  19.584 0.139 19.602 1.723 ;
     RECT  21.708 0.571 21.726 1.723 ;
     RECT  6.12 0.091 6.138 2.101 ;
     RECT  7.2 0.091 7.218 2.101 ;
     RECT  7.2 2.101 7.254 2.143 ;
     RECT  8.208 0.091 8.226 2.143 ;
     RECT  18.36 1.723 18.558 2.143 ;
     RECT  19.404 1.723 19.818 2.143 ;
     RECT  5.076 1.723 5.094 2.191 ;
     RECT  6.12 2.101 6.318 2.191 ;
     RECT  9.288 0.139 9.414 2.191 ;
     RECT  10.332 1.723 13.554 2.191 ;
     RECT  14.508 1.723 17.514 2.191 ;
     RECT  18.36 2.143 19.818 2.191 ;
     RECT  21.708 1.723 21.87 2.191 ;
     RECT  5.076 2.191 6.318 2.219 ;
     RECT  7.2 2.143 8.226 2.227 ;
     RECT  9.108 2.191 9.45 2.227 ;
     RECT  21.708 2.191 22.05 2.255 ;
     RECT  7.2 2.227 9.45 2.263 ;
     RECT  10.332 2.191 13.626 2.263 ;
     RECT  22.032 2.255 22.05 2.263 ;
     RECT  22.824 0.571 22.842 2.263 ;
     RECT  3.96 0.091 3.978 2.335 ;
     RECT  3.96 2.335 4.266 2.371 ;
     RECT  5.076 2.219 6.21 2.371 ;
     RECT  7.2 2.263 13.626 2.371 ;
     RECT  14.436 2.191 19.818 2.371 ;
     RECT  20.556 1.723 20.574 2.371 ;
     RECT  22.032 2.263 22.842 2.371 ;
     RECT  2.415 2.143 2.505 2.413 ;
     RECT  24.015 2.143 24.105 2.413 ;
     RECT  29.415 2.143 29.505 2.413 ;
     RECT  34.815 2.143 34.905 2.413 ;
     RECT  40.215 2.143 40.305 2.413 ;
     RECT  45.615 2.143 45.705 2.413 ;
     RECT  51.015 2.143 51.105 2.413 ;
     RECT  56.415 2.143 56.505 2.413 ;
     RECT  61.815 2.143 61.905 2.413 ;
     RECT  67.215 2.143 67.305 2.413 ;
     RECT  72.615 2.143 72.705 2.413 ;
     RECT  78.015 2.143 78.105 2.413 ;
     RECT  83.415 2.143 83.505 2.413 ;
     RECT  3.96 2.371 6.21 2.489 ;
     RECT  7.2 2.371 20.79 2.489 ;
     RECT  22.032 2.371 22.878 2.489 ;
     RECT  4.932 2.489 5.49 2.525 ;
     RECT  9.108 2.489 20.178 2.525 ;
     RECT  3.996 2.489 4.086 2.633 ;
     RECT  7.236 2.489 8.154 2.633 ;
     RECT  22.248 2.489 22.878 2.641 ;
     RECT  22.248 2.641 23.058 2.839 ;
     RECT  9.144 2.525 20.178 3.271 ;
     RECT  9.144 3.271 20.394 3.991 ;
     RECT  21.168 2.641 21.186 3.991 ;
     RECT  5.472 2.525 5.49 4.109 ;
     RECT  9.144 3.991 21.186 4.117 ;
     RECT  7.236 2.633 8.097 4.261 ;
     RECT  9.144 4.117 21.294 4.261 ;
     RECT  22.248 2.839 23.202 4.261 ;
     RECT  4.068 2.633 4.086 4.451 ;
     RECT  7.236 4.261 23.202 4.657 ;
     RECT  24.015 2.413 24.297 4.657 ;
     RECT  5.436 4.531 5.454 4.765 ;
     RECT  7.236 4.657 25.11 4.801 ;
     RECT  25.848 4.621 25.866 4.801 ;
     RECT  7.236 4.801 25.866 4.963 ;
     RECT  4.14 4.891 4.302 4.973 ;
     RECT  2.415 2.413 2.697 4.987 ;
     RECT  5.328 4.765 5.454 4.999 ;
     RECT  6.192 4.225 6.21 4.999 ;
     RECT  5.328 4.999 6.21 5.035 ;
     RECT  4.14 4.973 4.158 5.069 ;
     RECT  4.968 5.035 6.21 5.189 ;
     RECT  7.164 4.963 25.866 5.189 ;
     RECT  5.148 5.189 6.21 5.305 ;
     RECT  7.164 5.189 25.83 5.305 ;
     RECT  5.148 5.305 25.83 5.567 ;
     RECT  5.364 5.567 25.83 5.603 ;
     RECT  5.364 5.603 25.758 5.639 ;
     RECT  6.228 5.639 25.758 5.693 ;
     RECT  2.304 4.987 2.697 5.701 ;
     RECT  2.304 5.701 2.898 5.765 ;
     RECT  2.415 5.765 2.898 5.881 ;
     RECT  3.996 5.467 4.05 6.079 ;
     RECT  2.415 5.881 3.114 6.115 ;
     RECT  3.996 6.079 4.266 6.115 ;
     RECT  2.415 6.115 4.554 6.269 ;
     RECT  6.516 5.693 25.758 6.385 ;
     RECT  2.415 6.269 4.122 6.539 ;
     RECT  5.364 5.639 5.382 6.575 ;
     RECT  2.415 6.539 2.79 6.611 ;
     RECT  3.564 6.539 4.122 6.683 ;
     RECT  6.516 6.385 25.794 6.691 ;
     RECT  3.996 6.683 4.122 6.809 ;
     RECT  4.104 6.809 4.122 6.845 ;
     RECT  6.264 6.691 25.794 7.079 ;
     RECT  6.264 7.079 25.542 7.115 ;
     RECT  26.784 6.511 26.802 7.123 ;
     RECT  6.804 7.115 25.542 7.133 ;
     RECT  6.84 7.133 25.542 7.259 ;
     RECT  7.02 7.259 25.542 7.349 ;
     RECT  29.415 2.413 29.697 7.357 ;
     RECT  7.452 7.349 25.542 7.373 ;
     RECT  26.28 7.123 26.802 7.429 ;
     RECT  7.815 7.373 25.542 8.005 ;
     RECT  26.28 7.429 26.874 8.005 ;
     RECT  7.815 8.005 26.874 8.195 ;
     RECT  28.62 6.385 28.638 8.311 ;
     RECT  7.815 8.195 25.578 8.429 ;
     RECT  7.815 8.429 25.542 10.967 ;
     RECT  10.44 10.967 25.542 10.973 ;
     RECT  10.584 10.973 25.542 11.165 ;
     RECT  10.584 11.165 16.65 11.435 ;
     RECT  10.584 11.435 14.85 11.849 ;
     RECT  10.584 11.849 12.33 12.047 ;
     RECT  11.34 12.047 12.33 12.083 ;
     RECT  13.068 11.849 14.85 12.083 ;
     RECT  13.068 12.083 14.67 12.209 ;
     RECT  13.215 12.209 14.67 12.281 ;
     RECT  15.876 11.435 16.65 12.479 ;
     RECT  14.292 12.281 14.67 12.551 ;
     RECT  14.652 12.551 14.67 12.623 ;
     RECT  7.815 10.967 9.63 12.857 ;
     RECT  11.34 12.083 11.358 13.019 ;
     RECT  16.092 12.479 16.65 14.395 ;
     RECT  17.496 11.165 25.542 14.395 ;
     RECT  16.092 14.395 25.542 14.669 ;
     RECT  17.496 14.669 25.542 27.877 ;
     RECT  26.46 8.195 26.478 27.877 ;
     RECT  17.496 27.877 26.478 27.917 ;
     RECT  34.815 2.413 35.097 30.577 ;
     RECT  34.815 30.577 35.19 30.613 ;
     RECT  34.815 30.613 35.298 30.649 ;
     RECT  34.308 30.649 35.298 30.721 ;
     RECT  28.548 8.311 28.638 30.811 ;
     RECT  29.415 7.357 29.898 30.811 ;
     RECT  34.092 30.721 35.514 30.811 ;
     RECT  33.012 30.811 33.03 30.859 ;
     RECT  34.092 30.811 35.586 30.859 ;
     RECT  28.548 30.811 30.51 30.919 ;
     RECT  31.284 30.721 31.41 30.919 ;
     RECT  28.548 30.919 31.95 30.955 ;
     RECT  32.868 30.859 35.586 30.955 ;
     RECT  28.44 30.955 35.586 30.991 ;
     RECT  28.296 30.991 35.586 31.081 ;
     RECT  28.188 31.081 35.586 31.117 ;
     RECT  40.215 2.413 40.497 31.117 ;
     RECT  40.215 31.117 40.662 31.153 ;
     RECT  26.46 27.917 26.478 31.189 ;
     RECT  40.215 31.153 40.806 31.189 ;
     RECT  39.852 31.189 40.806 31.225 ;
     RECT  26.46 31.189 26.982 31.261 ;
     RECT  27.828 31.117 35.874 31.261 ;
     RECT  39.852 31.225 40.95 31.261 ;
     RECT  42.192 31.225 42.21 31.261 ;
     RECT  26.46 31.261 36.342 31.351 ;
     RECT  26.28 31.351 36.342 31.415 ;
     RECT  39.852 31.261 41.094 31.459 ;
     RECT  42.156 31.261 42.21 31.459 ;
     RECT  45.615 2.413 45.897 31.459 ;
     RECT  48.204 31.387 48.222 31.459 ;
     RECT  31.284 31.415 36.342 31.495 ;
     RECT  39.852 31.459 42.282 31.495 ;
     RECT  45.615 31.459 46.062 31.495 ;
     RECT  45.615 31.495 46.638 31.531 ;
     RECT  48.096 31.459 48.222 31.531 ;
     RECT  45.615 31.531 48.222 31.621 ;
     RECT  26.28 31.415 30.51 31.649 ;
     RECT  31.284 31.495 36.378 31.649 ;
     RECT  39.852 31.495 43.254 31.657 ;
     RECT  45.288 31.621 48.222 31.657 ;
     RECT  45.288 31.657 48.33 31.729 ;
     RECT  37.692 31.765 37.71 31.801 ;
     RECT  38.844 31.729 38.862 31.801 ;
     RECT  39.6 31.657 43.254 31.801 ;
     RECT  45.108 31.729 48.33 31.801 ;
     RECT  45.108 31.801 48.474 31.867 ;
     RECT  37.692 31.801 37.854 31.891 ;
     RECT  38.844 31.801 43.254 31.891 ;
     RECT  44.784 31.867 48.474 31.891 ;
     RECT  31.32 31.649 36.378 31.919 ;
     RECT  37.692 31.891 43.254 31.955 ;
     RECT  40.032 31.955 43.254 31.999 ;
     RECT  40.032 31.999 43.758 32.035 ;
     RECT  44.676 31.891 48.474 32.035 ;
     RECT  37.692 31.955 39.222 32.071 ;
     RECT  37.656 32.071 39.222 32.189 ;
     RECT  40.032 32.035 48.474 32.225 ;
     RECT  17.496 27.917 25.542 32.269 ;
     RECT  26.28 31.649 30.402 32.269 ;
     RECT  37.656 32.189 39.114 32.341 ;
     RECT  40.068 32.225 48.474 32.341 ;
     RECT  17.496 32.269 30.402 32.431 ;
     RECT  40.068 32.341 48.546 32.431 ;
     RECT  17.496 32.431 30.474 32.611 ;
     RECT  31.32 31.919 36.342 32.611 ;
     RECT  40.068 32.431 48.762 32.881 ;
     RECT  37.62 32.341 39.114 32.971 ;
     RECT  40.068 32.881 48.798 32.971 ;
     RECT  37.62 32.971 48.834 33.043 ;
     RECT  37.44 33.043 48.834 33.115 ;
     RECT  37.26 33.115 48.834 33.151 ;
     RECT  17.496 32.611 36.342 33.241 ;
     RECT  37.26 33.151 48.942 33.241 ;
     RECT  17.496 33.241 48.942 33.269 ;
     RECT  17.496 33.269 48.834 33.809 ;
     RECT  17.496 33.809 41.526 33.845 ;
     RECT  42.3 33.809 48.834 33.845 ;
     RECT  17.496 33.845 41.382 34.151 ;
     RECT  42.336 33.845 48.834 34.187 ;
     RECT  17.496 34.151 31.374 34.349 ;
     RECT  42.336 34.187 48.402 34.591 ;
     RECT  12.312 12.083 12.33 34.735 ;
     RECT  32.112 34.151 41.382 34.735 ;
     RECT  42.228 34.591 48.402 34.735 ;
     RECT  12.312 34.735 12.366 34.763 ;
     RECT  32.112 34.735 48.402 34.889 ;
     RECT  28.116 34.349 31.374 35.005 ;
     RECT  32.112 34.889 41.274 35.005 ;
     RECT  42.12 34.889 48.402 35.041 ;
     RECT  42.12 35.041 48.51 35.159 ;
     RECT  17.496 34.349 27.198 35.203 ;
     RECT  28.116 35.005 41.274 35.203 ;
     RECT  17.496 35.203 41.274 35.671 ;
     RECT  42.12 35.159 48.438 35.671 ;
     RECT  16.092 14.669 16.65 35.947 ;
     RECT  17.496 35.671 48.438 35.947 ;
     RECT  15.948 35.947 48.438 36.049 ;
     RECT  15.948 36.049 48.69 36.077 ;
     RECT  15.012 36.121 15.03 36.211 ;
     RECT  28.368 36.077 48.69 36.319 ;
     RECT  13.215 12.281 13.497 36.355 ;
     RECT  14.796 36.211 15.03 36.355 ;
     RECT  28.368 36.319 49.086 36.383 ;
     RECT  14.544 36.355 15.03 36.391 ;
     RECT  15.948 36.077 27.378 36.391 ;
     RECT  28.404 36.383 49.086 36.515 ;
     RECT  28.404 36.515 44.37 36.545 ;
     RECT  28.512 36.545 44.37 36.581 ;
     RECT  13.215 36.355 13.806 36.661 ;
     RECT  14.544 36.391 27.378 36.661 ;
     RECT  13.215 36.661 27.378 36.823 ;
     RECT  10.584 12.047 10.602 36.895 ;
     RECT  11.376 36.859 11.394 36.895 ;
     RECT  10.512 36.895 10.602 36.931 ;
     RECT  11.34 36.895 11.394 36.931 ;
     RECT  12.348 34.763 12.366 36.931 ;
     RECT  13.215 36.823 27.414 37.093 ;
     RECT  28.548 36.581 44.37 37.121 ;
     RECT  13.215 37.093 27.486 37.129 ;
     RECT  28.548 37.121 44.334 37.319 ;
     RECT  10.512 36.931 12.366 37.363 ;
     RECT  10.44 37.363 12.366 37.435 ;
     RECT  13.215 37.129 27.702 37.435 ;
     RECT  28.548 37.319 44.262 37.435 ;
     RECT  45.144 36.515 49.086 37.435 ;
     RECT  9.612 12.857 9.63 37.471 ;
     RECT  45.144 37.435 49.374 37.589 ;
     RECT  45.144 37.589 47.25 37.625 ;
     RECT  5.4 37.201 5.418 37.633 ;
     RECT  9.36 37.471 9.63 37.633 ;
     RECT  10.44 37.435 44.262 37.633 ;
     RECT  5.148 37.633 5.418 37.741 ;
     RECT  9.36 37.633 44.262 37.859 ;
     RECT  7.815 12.857 8.55 37.975 ;
     RECT  47.988 37.589 49.374 38.003 ;
     RECT  48.096 38.003 49.374 38.011 ;
     RECT  9.576 37.859 44.262 38.039 ;
     RECT  41.256 38.039 44.262 38.101 ;
     RECT  45.144 37.625 46.746 38.101 ;
     RECT  41.256 38.101 46.746 38.129 ;
     RECT  5.112 37.741 5.418 38.173 ;
     RECT  9.576 38.039 40.497 38.201 ;
     RECT  41.256 38.129 41.274 38.237 ;
     RECT  4.392 38.173 5.418 38.281 ;
     RECT  6.156 38.209 6.174 38.281 ;
     RECT  42.048 38.129 46.746 38.399 ;
     RECT  3.96 38.281 6.174 38.407 ;
     RECT  3.888 38.407 6.246 38.443 ;
     RECT  42.048 38.399 46.674 38.543 ;
     RECT  42.588 38.543 46.674 38.669 ;
     RECT  48.096 38.011 49.554 38.705 ;
     RECT  7.815 37.975 8.838 38.713 ;
     RECT  9.576 38.201 13.626 38.713 ;
     RECT  42.588 38.669 44.082 38.717 ;
     RECT  44.064 38.717 44.082 38.741 ;
     RECT  48.24 38.705 48.654 38.741 ;
     RECT  48.24 38.741 48.258 38.939 ;
     RECT  49.536 38.705 49.554 39.011 ;
     RECT  7.416 38.713 13.626 39.055 ;
     RECT  14.436 38.201 40.497 39.209 ;
     RECT  45.144 38.669 46.674 39.209 ;
     RECT  3.528 38.443 6.246 39.217 ;
     RECT  14.436 39.209 35.622 39.245 ;
     RECT  36.396 39.209 40.497 39.245 ;
     RECT  36.54 39.245 40.497 39.253 ;
     RECT  36.54 39.253 40.77 39.281 ;
     RECT  6.984 39.055 13.626 39.289 ;
     RECT  14.436 39.245 35.586 39.289 ;
     RECT  37.224 39.281 40.77 39.317 ;
     RECT  3.456 39.217 6.246 39.325 ;
     RECT  6.984 39.289 35.586 39.325 ;
     RECT  3.456 39.325 35.586 39.893 ;
     RECT  42.588 38.717 43.146 39.901 ;
     RECT  45.144 39.209 46.566 39.901 ;
     RECT  42.156 39.901 43.146 40.099 ;
     RECT  41.904 40.099 43.146 40.135 ;
     RECT  44.532 39.901 46.566 40.135 ;
     RECT  2.415 6.611 2.697 40.171 ;
     RECT  3.456 39.893 5.418 40.171 ;
     RECT  6.156 39.893 35.586 40.171 ;
     RECT  41.724 40.135 43.146 40.297 ;
     RECT  41.688 40.297 43.146 40.333 ;
     RECT  37.332 39.317 40.77 40.369 ;
     RECT  41.688 40.333 43.182 40.369 ;
     RECT  43.992 40.135 46.566 40.369 ;
     RECT  41.688 40.369 46.566 40.411 ;
     RECT  6.156 40.171 35.982 40.441 ;
     RECT  2.415 40.171 5.418 40.639 ;
     RECT  6.156 40.441 36.27 40.639 ;
     RECT  2.415 40.639 36.27 40.909 ;
     RECT  37.224 40.369 40.77 40.909 ;
     RECT  2.415 40.909 40.77 40.981 ;
     RECT  41.508 40.411 46.566 40.981 ;
     RECT  2.415 40.981 46.566 42.605 ;
     RECT  2.415 42.605 13.986 42.989 ;
     RECT  3.42 42.989 13.986 43.375 ;
     RECT  14.724 42.605 46.566 43.375 ;
     RECT  3.42 43.375 46.566 43.601 ;
     RECT  26.496 43.601 46.566 43.645 ;
     RECT  2.415 42.989 2.697 44.419 ;
     RECT  3.42 43.601 25.722 44.419 ;
     RECT  2.415 44.419 25.722 44.455 ;
     RECT  2.415 44.455 25.758 44.491 ;
     RECT  26.496 43.645 47.106 44.491 ;
     RECT  2.415 44.491 47.394 44.681 ;
     RECT  7.092 44.681 47.394 45.265 ;
     RECT  7.092 45.265 47.502 45.535 ;
     RECT  7.092 45.535 47.718 45.689 ;
     RECT  2.415 44.681 6.354 46.075 ;
     RECT  7.092 45.689 47.502 46.075 ;
     RECT  2.415 46.075 47.502 46.373 ;
     RECT  7.092 46.373 47.502 47.039 ;
     RECT  2.415 46.373 6.354 47.155 ;
     RECT  7.092 47.039 46.926 47.155 ;
     RECT  2.415 47.155 46.926 47.183 ;
     RECT  2.415 47.183 46.854 48.001 ;
     RECT  2.415 48.001 47.322 48.199 ;
     RECT  2.415 48.199 47.358 48.811 ;
     RECT  2.415 48.811 47.502 48.929 ;
     RECT  47.34 48.929 47.502 48.965 ;
     RECT  2.415 48.929 46.242 49.037 ;
     RECT  47.34 48.965 47.394 49.199 ;
     RECT  2.415 49.037 46.206 49.235 ;
     RECT  2.415 49.235 46.134 49.541 ;
     RECT  2.415 49.541 26.226 49.739 ;
     RECT  27.144 49.541 46.134 50.009 ;
     RECT  39.24 50.009 46.134 50.431 ;
     RECT  2.415 49.739 25.83 50.665 ;
     RECT  2.415 50.665 25.902 50.971 ;
     RECT  27.144 50.009 38.43 50.971 ;
     RECT  39.24 50.431 46.206 50.971 ;
     RECT  2.415 50.971 46.206 51.089 ;
     RECT  2.415 51.089 16.866 51.233 ;
     RECT  17.604 51.089 46.206 51.359 ;
     RECT  17.604 51.359 38.43 51.431 ;
     RECT  17.604 51.431 26.262 51.437 ;
     RECT  37.404 51.431 38.43 51.539 ;
     RECT  27.072 51.431 36.63 51.581 ;
     RECT  2.415 51.233 16.398 51.587 ;
     RECT  51.015 2.413 51.297 51.587 ;
     RECT  56.415 2.413 56.697 51.587 ;
     RECT  61.815 2.413 62.097 51.587 ;
     RECT  67.215 2.413 67.497 51.587 ;
     RECT  72.615 2.413 72.897 51.587 ;
     RECT  78.015 2.413 78.297 51.587 ;
     RECT  83.415 2.413 83.697 51.587 ;
     RECT  3.312 51.587 16.398 51.629 ;
     RECT  27.072 51.581 36.558 51.629 ;
     RECT  37.404 51.539 38.358 51.629 ;
     RECT  39.168 51.359 46.17 51.629 ;
     RECT  47.34 49.199 47.358 51.629 ;
     RECT  7.815 51.629 15.966 51.665 ;
     RECT  33.732 51.629 35.658 51.701 ;
     RECT  3.312 51.629 6.822 51.737 ;
     RECT  9 51.665 9.522 51.737 ;
     RECT  10.26 51.665 13.305 51.737 ;
     RECT  17.64 51.437 26.262 51.737 ;
     RECT  10.944 51.737 13.305 51.773 ;
     RECT  14.148 51.665 15.966 51.773 ;
     RECT  17.64 51.737 18.846 51.779 ;
     RECT  3.312 51.737 4.194 51.809 ;
     RECT  11.124 51.773 13.305 51.809 ;
     RECT  19.8 51.737 19.818 51.809 ;
     RECT  27.072 51.629 32.598 51.809 ;
     RECT  33.732 51.701 33.75 51.809 ;
     RECT  36.54 51.629 36.558 51.809 ;
     RECT  40.068 51.629 46.134 51.809 ;
     RECT  3.816 51.809 4.194 51.821 ;
     RECT  5.004 51.737 6.822 51.821 ;
     RECT  9 51.737 9.45 51.821 ;
     RECT  17.64 51.779 18.705 51.821 ;
     RECT  31.572 51.809 32.598 51.821 ;
     RECT  37.512 51.629 38.07 51.821 ;
     RECT  40.068 51.809 41.598 51.821 ;
     RECT  2.415 51.587 2.505 51.857 ;
     RECT  7.815 51.665 8.262 51.857 ;
     RECT  11.268 51.809 13.305 51.857 ;
     RECT  17.892 51.821 18.705 51.857 ;
     RECT  34.815 51.701 35.658 51.857 ;
     RECT  45.288 51.809 46.134 51.857 ;
     RECT  51.015 51.587 51.105 51.857 ;
     RECT  56.415 51.587 56.505 51.857 ;
     RECT  61.815 51.587 61.905 51.857 ;
     RECT  67.215 51.587 67.305 51.857 ;
     RECT  72.615 51.587 72.705 51.857 ;
     RECT  78.015 51.587 78.105 51.857 ;
     RECT  83.415 51.587 83.505 51.857 ;
     RECT  5.004 51.821 6.246 51.869 ;
     RECT  7.956 51.857 8.262 51.869 ;
     RECT  9.432 51.821 9.45 51.869 ;
     RECT  11.268 51.857 12.51 51.869 ;
     RECT  14.148 51.773 15.822 51.869 ;
     RECT  17.892 51.857 17.91 51.869 ;
     RECT  28.836 51.809 30.69 51.869 ;
     RECT  37.512 51.821 37.962 51.869 ;
     RECT  46.116 51.857 46.134 51.869 ;
     RECT  12.132 51.869 12.15 51.917 ;
     RECT  42.408 51.809 44.262 51.917 ;
     RECT  7.956 51.869 8.19 51.965 ;
     RECT  35.28 51.857 35.658 52.013 ;
     RECT  40.068 51.821 41.526 52.013 ;
     RECT  20.664 51.737 26.262 52.109 ;
     RECT  27.072 51.809 27.81 52.445 ;
     RECT  28.836 51.869 30.366 52.445 ;
     RECT  39.168 51.629 39.186 52.445 ;
     RECT  5.004 51.869 5.49 52.493 ;
     RECT  14.148 51.869 14.238 52.493 ;
     RECT  28.836 52.445 29.286 52.493 ;
     RECT  30.132 52.445 30.366 52.493 ;
     RECT  31.572 51.821 32.418 52.493 ;
     RECT  40.104 52.013 41.526 52.493 ;
     RECT  28.836 52.493 29.07 52.541 ;
     RECT  42.876 51.917 44.262 52.541 ;
     RECT  41.4 52.493 41.526 52.973 ;
     RECT  43.488 52.541 44.262 52.973 ;
     RECT  11.268 51.869 11.286 53.021 ;
     RECT  28.836 52.541 29.034 53.021 ;
     RECT  30.348 52.493 30.366 53.021 ;
     RECT  31.572 52.493 32.238 53.021 ;
     RECT  41.4 52.973 41.454 53.021 ;
     RECT  43.596 52.973 44.262 53.021 ;
     RECT  45.288 51.857 45.306 53.021 ;
     RECT  5.004 52.493 5.022 53.069 ;
     RECT  7.956 51.965 7.974 53.069 ;
     RECT  14.22 52.493 14.238 53.069 ;
     RECT  24.156 52.109 26.262 53.069 ;
     RECT  27.072 52.445 27.666 53.069 ;
     RECT  28.836 53.021 28.926 53.069 ;
     RECT  40.104 52.493 40.122 53.069 ;
     RECT  25.272 53.069 25.902 53.117 ;
     RECT  27.072 53.069 27.558 53.117 ;
     RECT  28.836 53.069 28.854 53.117 ;
     RECT  25.272 53.117 25.83 53.165 ;
     RECT  25.272 53.165 25.29 53.213 ;
     RECT  35.64 52.013 35.658 53.659 ;
     RECT  12.312 53.659 12.33 53.707 ;
     RECT  24.372 53.069 24.462 53.789 ;
     RECT  37.512 51.869 37.566 53.789 ;
     RECT  12.312 53.707 12.402 53.837 ;
     RECT  20.664 52.109 23.238 53.837 ;
     RECT  35.424 53.659 35.658 53.837 ;
     RECT  3.816 51.821 3.834 53.885 ;
     RECT  12.384 53.837 12.402 53.885 ;
     RECT  20.736 53.837 23.238 53.885 ;
     RECT  24.372 53.789 24.39 53.885 ;
     RECT  27.072 53.117 27.09 53.885 ;
     RECT  31.572 53.021 31.59 53.885 ;
     RECT  35.64 53.837 35.658 53.885 ;
     RECT  37.512 53.789 37.53 53.885 ;
     RECT  41.436 53.021 41.454 53.885 ;
     RECT  44.244 53.021 44.262 53.885 ;
     RECT  21.06 53.885 21.078 53.981 ;
     RECT  26.1 53.851 26.118 53.981 ;
    LAYER M4 ;
     RECT  0.06 4.032 0.227 5.016 ;
     RECT  0.227 4.992 2.408 5.016 ;
     RECT  0.181 27.696 2.408 27.72 ;
     RECT  2.293 40.368 2.408 40.392 ;
     RECT  2.293 42.768 2.408 42.792 ;
     RECT  2.293 44.448 2.408 44.472 ;
     RECT  2.408 2.148 2.512 51.852 ;
     RECT  2.512 2.418 2.704 51.582 ;
     RECT  2.704 40.272 2.837 40.392 ;
     RECT  2.704 44.976 2.867 46.536 ;
     RECT  2.867 45.696 2.909 46.296 ;
     RECT  2.837 40.272 3.692 40.296 ;
     RECT  2.704 48.432 3.733 48.456 ;
     RECT  2.704 38.688 3.779 39.048 ;
     RECT  3.692 40.176 3.779 40.296 ;
     RECT  2.909 45.84 3.881 46.296 ;
     RECT  3.881 45.936 3.917 46.296 ;
     RECT  3.733 47.712 3.925 48.456 ;
     RECT  2.704 41.952 3.949 41.976 ;
     RECT  3.779 40.272 4.021 40.296 ;
     RECT  3.949 0.096 4.067 0.12 ;
     RECT  2.704 6.24 4.163 6.264 ;
     RECT  2.704 50.736 4.165 51.192 ;
     RECT  3.925 47.712 4.169 49.416 ;
     RECT  3.949 41.952 4.201 42.888 ;
     RECT  3.949 43.968 4.201 43.992 ;
     RECT  4.117 5.04 4.273 5.256 ;
     RECT  4.165 50.736 4.345 51.816 ;
     RECT  4.169 48.96 4.417 49.416 ;
     RECT  4.345 50.592 4.417 51.816 ;
     RECT  4.201 41.952 4.453 43.992 ;
     RECT  4.453 41.952 4.889 44.472 ;
     RECT  3.805 53.856 4.993 53.88 ;
     RECT  4.169 47.712 5.033 47.928 ;
     RECT  4.993 53.04 5.123 53.88 ;
     RECT  4.889 41.952 5.137 41.976 ;
     RECT  5.065 1.728 5.149 1.752 ;
     RECT  4.273 4.944 5.177 5.256 ;
     RECT  4.417 48.96 5.314 51.816 ;
     RECT  5.033 47.904 5.357 47.928 ;
     RECT  5.123 53.04 5.411 53.064 ;
     RECT  5.314 48.96 5.461 51.864 ;
     RECT  4.889 43.008 5.653 44.472 ;
     RECT  3.917 45.936 5.653 45.96 ;
     RECT  3.779 38.688 5.681 38.712 ;
     RECT  5.653 43.008 5.681 45.96 ;
     RECT  5.137 41.76 5.821 41.976 ;
     RECT  5.461 48.96 5.852 52.488 ;
     RECT  5.681 43.392 5.861 45.96 ;
     RECT  5.861 43.488 5.897 45.96 ;
     RECT  5.852 48.816 5.987 52.488 ;
     RECT  4.021 40.272 6.073 40.392 ;
     RECT  5.821 41.472 6.073 41.976 ;
     RECT  6.109 0.096 6.193 0.12 ;
     RECT  5.177 4.944 6.217 5.208 ;
     RECT  6.073 40.272 6.217 41.976 ;
     RECT  5.987 48.816 6.301 51.864 ;
     RECT  6.217 4.944 6.505 5.688 ;
     RECT  6.325 53.808 6.611 53.832 ;
     RECT  5.897 43.536 6.689 45.96 ;
     RECT  6.301 48.816 6.865 51.816 ;
     RECT  6.793 7.104 6.901 7.128 ;
     RECT  6.865 48.72 7.369 51.816 ;
     RECT  6.505 4.944 7.441 6.024 ;
     RECT  6.901 7.104 7.441 7.224 ;
     RECT  6.689 43.632 7.693 45.96 ;
     RECT  7.441 4.944 7.808 7.368 ;
     RECT  2.704 27.696 7.808 27.72 ;
     RECT  6.217 39.504 7.808 41.976 ;
     RECT  7.693 43.632 7.808 46.056 ;
     RECT  7.369 48.48 7.808 51.816 ;
     RECT  7.808 2.148 7.912 51.852 ;
     RECT  7.912 2.418 8.104 51.852 ;
     RECT  8.104 48.48 8.117 51.852 ;
     RECT  8.117 48.48 8.201 51.96 ;
     RECT  8.104 43.632 8.243 46.056 ;
     RECT  7.189 0.096 8.291 0.12 ;
     RECT  8.243 43.632 8.345 45.528 ;
     RECT  7.945 53.04 8.387 53.064 ;
     RECT  8.104 8.544 8.453 8.568 ;
     RECT  8.201 48.48 8.813 51.864 ;
     RECT  8.104 47.136 9.173 47.304 ;
     RECT  8.813 48.864 9.251 51.864 ;
     RECT  9.251 48.96 9.317 51.864 ;
     RECT  9.277 0.096 9.36 0.12 ;
     RECT  9.36 0.096 9.361 0.168 ;
     RECT  9.173 47.136 9.425 47.208 ;
     RECT  8.104 39.36 9.461 42.072 ;
     RECT  9.317 51.216 9.461 51.864 ;
     RECT  8.104 4.944 9.601 7.464 ;
     RECT  8.104 38.016 9.637 38.04 ;
     RECT  9.461 39.504 9.637 42.072 ;
     RECT  9.601 4.944 9.673 7.752 ;
     RECT  9.565 8.736 9.673 8.76 ;
     RECT  9.317 48.96 9.677 50.184 ;
     RECT  8.345 43.632 9.817 44.952 ;
     RECT  9.637 39.504 9.853 42.504 ;
     RECT  9.853 39.504 9.889 42.552 ;
     RECT  9.817 43.632 9.889 45.048 ;
     RECT  9.637 38.016 10.033 38.184 ;
     RECT  9.889 39.504 10.249 45.048 ;
     RECT  9.421 46.08 10.249 46.104 ;
     RECT  9.677 48.96 10.249 48.984 ;
     RECT  9.673 4.944 10.285 8.76 ;
     RECT  9.361 0.144 10.429 0.168 ;
     RECT  10.429 0.096 10.453 0.168 ;
     RECT  9.677 49.968 10.46 50.184 ;
     RECT  9.461 51.216 10.46 51.384 ;
     RECT  10.46 36.912 10.501 36.936 ;
     RECT  10.033 38.016 10.501 38.424 ;
     RECT  10.501 36.912 10.547 38.424 ;
     RECT  10.547 37.632 10.645 38.424 ;
     RECT  10.249 39.504 10.645 46.104 ;
     RECT  9.425 47.184 10.645 47.208 ;
     RECT  10.46 49.968 10.709 51.384 ;
     RECT  10.249 48.432 10.741 48.984 ;
     RECT  10.709 49.968 10.741 51.432 ;
     RECT  10.453 0.096 10.787 0.6 ;
     RECT  10.787 0.096 10.883 0.168 ;
     RECT  10.897 3.456 10.933 3.48 ;
     RECT  10.933 3.408 11.153 3.48 ;
     RECT  10.753 1.728 11.285 1.752 ;
     RECT  11.285 1.728 11.293 1.848 ;
     RECT  10.285 4.944 11.293 9.048 ;
     RECT  10.741 48.432 11.329 51.432 ;
     RECT  11.293 1.728 11.401 2.28 ;
     RECT  11.293 4.944 11.401 9.912 ;
     RECT  10.429 10.944 11.401 10.968 ;
     RECT  11.329 48.336 11.401 51.432 ;
     RECT  11.257 52.992 11.459 53.016 ;
     RECT  10.645 37.632 11.473 47.208 ;
     RECT  11.401 48.336 11.473 51.816 ;
     RECT  11.401 4.32 11.513 10.968 ;
     RECT  11.401 1.152 11.689 2.28 ;
     RECT  11.473 37.632 11.797 51.816 ;
     RECT  11.797 37.632 11.989 51.864 ;
     RECT  11.989 37.632 12.182 51.912 ;
     RECT  10.883 0.096 12.269 0.12 ;
     RECT  11.689 1.152 12.365 2.328 ;
     RECT  12.257 53.664 12.373 53.832 ;
     RECT  12.373 53.664 12.419 53.88 ;
     RECT  12.157 3.792 12.437 3.816 ;
     RECT  12.365 0.576 12.449 2.328 ;
     RECT  12.419 53.856 12.457 53.88 ;
     RECT  12.182 37.632 12.521 51.864 ;
     RECT  12.437 3.408 12.661 3.816 ;
     RECT  11.513 4.944 12.661 10.968 ;
     RECT  12.449 1.152 13.093 2.328 ;
     RECT  12.661 3.408 13.093 10.968 ;
     RECT  13.093 1.152 13.208 10.968 ;
     RECT  8.104 27.696 13.208 27.72 ;
     RECT  12.521 37.632 13.208 51.852 ;
     RECT  13.208 1.152 13.385 51.852 ;
     RECT  13.385 1.728 13.504 51.852 ;
     RECT  13.504 3.648 13.673 12.504 ;
     RECT  13.673 3.648 13.708 3.912 ;
     RECT  14.137 52.464 14.209 52.488 ;
     RECT  13.673 4.944 14.249 12.504 ;
     RECT  14.249 4.944 14.285 11.496 ;
     RECT  14.209 52.464 14.339 53.064 ;
     RECT  14.249 12.48 14.435 12.504 ;
     RECT  13.504 39.216 14.485 51.384 ;
     RECT  14.339 52.464 14.485 52.488 ;
     RECT  13.504 36.528 14.533 37.656 ;
     RECT  14.485 39.216 14.533 52.488 ;
     RECT  14.533 36.528 14.645 52.488 ;
     RECT  13.504 1.728 14.669 1.752 ;
     RECT  14.645 38.352 14.723 52.488 ;
     RECT  14.669 1.728 14.749 2.328 ;
     RECT  13.708 3.648 14.749 3.672 ;
     RECT  14.285 4.944 14.749 11.4 ;
     RECT  14.749 1.728 14.753 11.4 ;
     RECT  13.237 0.096 14.825 0.12 ;
     RECT  14.753 1.728 14.965 1.8 ;
     RECT  14.753 2.832 15.155 11.4 ;
     RECT  14.869 0.144 15.349 0.168 ;
     RECT  14.965 1.152 15.349 1.8 ;
     RECT  15.155 3.936 15.509 11.4 ;
     RECT  14.645 36.528 15.509 37.032 ;
     RECT  14.723 38.352 15.689 51.864 ;
     RECT  15.349 0.144 15.821 1.8 ;
     RECT  15.509 3.936 15.833 10.728 ;
     RECT  15.689 49.536 15.833 51.864 ;
     RECT  15.821 0.144 15.901 1.848 ;
     RECT  15.155 2.832 15.901 2.856 ;
     RECT  15.509 36.528 15.937 36.552 ;
     RECT  15.833 49.536 15.941 51.144 ;
     RECT  15.865 12 15.949 12.024 ;
     RECT  15.941 49.536 15.971 50.76 ;
     RECT  15.689 38.352 16.049 48.456 ;
     RECT  15.901 0.144 16.067 2.856 ;
     RECT  15.971 50.544 16.157 50.76 ;
     RECT  16.067 0.144 16.213 0.552 ;
     RECT  16.049 43.536 16.409 48.456 ;
     RECT  16.067 1.728 16.441 2.856 ;
     RECT  16.213 0.096 16.561 0.552 ;
     RECT  15.971 49.536 16.625 49.56 ;
     RECT  13.504 14.64 16.913 14.664 ;
     RECT  16.157 50.736 16.949 50.76 ;
     RECT  16.049 38.352 17.017 42.504 ;
     RECT  16.441 1.728 17.077 2.952 ;
     RECT  17.077 1.152 17.309 2.952 ;
     RECT  17.017 38.256 17.413 42.504 ;
     RECT  16.409 43.536 17.413 48.312 ;
     RECT  17.309 1.152 17.425 2.904 ;
     RECT  17.365 51.312 17.461 51.336 ;
     RECT  15.833 3.984 17.507 10.728 ;
     RECT  17.425 1.152 17.525 1.176 ;
     RECT  17.461 51.312 17.557 51.432 ;
     RECT  17.557 51.312 17.653 51.816 ;
     RECT  17.653 51.312 17.921 51.864 ;
     RECT  15.937 35.952 18.061 36.552 ;
     RECT  18.061 35.952 18.097 37.08 ;
     RECT  17.413 38.256 18.097 48.312 ;
     RECT  18.097 35.952 18.133 48.312 ;
     RECT  16.561 0.096 18.236 0.168 ;
     RECT  17.425 2.304 18.277 2.904 ;
     RECT  18.236 0.096 18.281 0.552 ;
     RECT  18.281 0.144 18.323 0.552 ;
     RECT  18.373 53.808 18.469 53.832 ;
     RECT  18.277 2.304 18.485 3.432 ;
     RECT  18.469 53.712 18.563 53.832 ;
     RECT  18.485 1.728 18.608 3.432 ;
     RECT  17.507 4.512 18.608 10.728 ;
     RECT  17.053 14.4 18.608 14.424 ;
     RECT  13.504 27.696 18.608 27.72 ;
     RECT  17.221 32.592 18.608 32.616 ;
     RECT  18.133 35.76 18.608 48.312 ;
     RECT  18.169 49.584 18.608 49.608 ;
     RECT  17.921 51.312 18.608 51.852 ;
     RECT  18.563 53.712 18.659 53.736 ;
     RECT  18.608 1.728 18.712 51.852 ;
     RECT  18.712 1.728 18.857 51.768 ;
     RECT  18.857 1.728 18.904 51.72 ;
     RECT  18.904 1.728 18.965 2.376 ;
     RECT  18.904 48.192 19.073 49.608 ;
     RECT  18.904 34.464 19.109 47.16 ;
     RECT  18.904 4.512 19.325 10.728 ;
     RECT  18.904 50.832 19.541 51.72 ;
     RECT  18.323 0.144 19.613 0.168 ;
     RECT  19.073 48.192 19.613 49.128 ;
     RECT  19.109 34.464 19.685 37.992 ;
     RECT  19.325 4.512 19.757 10.68 ;
     RECT  19.685 34.464 20.081 37.944 ;
     RECT  18.904 3.408 20.089 3.432 ;
     RECT  18.904 32.592 20.261 32.616 ;
     RECT  19.757 4.56 20.365 10.68 ;
     RECT  19.109 39.216 20.401 47.16 ;
     RECT  20.533 53.856 20.609 53.88 ;
     RECT  20.365 4.56 20.653 11.304 ;
     RECT  20.653 4.56 20.657 11.736 ;
     RECT  20.609 53.808 20.677 53.88 ;
     RECT  20.081 34.656 20.689 37.944 ;
     RECT  20.401 39.216 20.689 47.256 ;
     RECT  19.613 48.24 20.689 49.128 ;
     RECT  20.689 48.24 20.725 49.464 ;
     RECT  19.541 50.832 20.725 51.672 ;
     RECT  18.965 1.728 20.771 1.752 ;
     RECT  20.677 53.664 20.773 53.88 ;
     RECT  20.657 10.656 20.837 11.736 ;
     RECT  20.837 10.656 20.981 10.68 ;
     RECT  20.773 53.616 21.049 53.88 ;
     RECT  20.869 11.904 21.085 11.928 ;
     RECT  21.049 53.616 21.157 53.976 ;
     RECT  21.085 11.904 21.253 11.976 ;
     RECT  20.689 34.656 21.293 47.256 ;
     RECT  20.725 48.24 21.293 51.672 ;
     RECT  21.293 34.656 21.395 51.672 ;
     RECT  20.941 32.064 21.637 32.52 ;
     RECT  21.395 34.656 21.665 47.16 ;
     RECT  21.665 38.448 21.701 47.16 ;
     RECT  21.253 11.904 21.724 12.936 ;
     RECT  20.657 4.56 21.737 9.672 ;
     RECT  21.697 0.576 21.827 0.6 ;
     RECT  21.637 32.064 21.841 33.384 ;
     RECT  21.733 13.344 21.845 13.368 ;
     RECT  21.841 32.016 21.881 33.384 ;
     RECT  21.841 1.728 21.925 1.752 ;
     RECT  21.841 10.8 21.925 10.824 ;
     RECT  21.395 49.056 21.953 51.672 ;
     RECT  21.881 33.072 21.971 33.384 ;
     RECT  21.949 11.76 22.033 11.784 ;
     RECT  21.665 34.656 22.097 37.08 ;
     RECT  21.971 33.072 22.133 33.096 ;
     RECT  22.097 34.656 22.241 35.496 ;
     RECT  21.701 38.448 22.313 47.064 ;
     RECT  21.737 4.56 22.349 9.48 ;
     RECT  21.953 49.056 22.525 49.128 ;
     RECT  22.313 39.456 22.669 47.064 ;
     RECT  22.705 13.056 22.789 13.08 ;
     RECT  21.637 30.816 22.849 30.84 ;
     RECT  21.881 32.016 22.853 32.04 ;
     RECT  22.525 48.96 22.885 49.128 ;
     RECT  22.849 30.816 22.889 30.936 ;
     RECT  22.669 39.456 22.957 47.16 ;
     RECT  22.885 48.192 22.957 49.128 ;
     RECT  22.813 0.576 22.979 0.6 ;
     RECT  21.157 53.04 22.979 53.976 ;
     RECT  22.889 30.912 23.029 30.936 ;
     RECT  22.241 34.656 23.029 35.256 ;
     RECT  22.979 53.136 23.075 53.976 ;
     RECT  21.953 50.352 23.173 51.672 ;
     RECT  23.029 33.936 23.281 35.256 ;
     RECT  23.173 50.352 23.353 51.768 ;
     RECT  23.353 50.352 23.365 51.912 ;
     RECT  22.313 38.448 23.381 38.472 ;
     RECT  22.957 39.456 23.381 49.128 ;
     RECT  23.365 50.16 23.389 51.912 ;
     RECT  23.381 38.448 23.413 49.128 ;
     RECT  23.389 50.16 23.413 52.008 ;
     RECT  22.097 36.528 23.713 37.08 ;
     RECT  23.281 33.024 23.749 35.256 ;
     RECT  23.713 36.528 23.749 37.128 ;
     RECT  23.749 33.024 23.785 37.128 ;
     RECT  23.413 38.448 23.785 52.008 ;
     RECT  23.785 33.024 23.929 52.008 ;
     RECT  22.349 4.704 24.008 9.48 ;
     RECT  18.904 14.4 24.008 14.424 ;
     RECT  18.904 27.696 24.008 27.72 ;
     RECT  23.029 30.912 24.008 31.32 ;
     RECT  23.929 33.024 24.008 52.104 ;
     RECT  24.008 2.148 24.112 52.104 ;
     RECT  24.112 2.418 24.145 52.104 ;
     RECT  23.075 53.856 24.145 53.976 ;
     RECT  24.145 2.418 24.304 53.976 ;
     RECT  24.304 32.592 24.445 48.456 ;
     RECT  24.304 14.4 24.707 14.424 ;
     RECT  24.304 4.704 24.725 7.752 ;
     RECT  24.445 32.592 24.725 37.464 ;
     RECT  24.304 9.072 24.803 9.288 ;
     RECT  24.304 30.912 24.803 31.176 ;
     RECT  24.803 9.072 24.841 9.096 ;
     RECT  24.304 26.784 24.899 27.912 ;
     RECT  24.725 5.136 24.905 7.752 ;
     RECT  24.899 27.696 25.013 27.912 ;
     RECT  24.905 5.136 25.193 6.984 ;
     RECT  25.193 5.184 25.324 6.984 ;
     RECT  25.324 6.432 25.337 6.984 ;
     RECT  24.304 49.584 25.481 53.976 ;
     RECT  25.324 5.184 25.523 5.208 ;
     RECT  25.481 49.584 25.625 49.608 ;
     RECT  25.481 50.592 25.667 53.976 ;
     RECT  25.667 50.592 25.733 51.336 ;
     RECT  24.725 33.936 25.801 37.464 ;
     RECT  24.445 38.448 25.801 48.456 ;
     RECT  25.337 6.432 25.805 6.456 ;
     RECT  25.667 52.464 25.859 53.976 ;
     RECT  25.801 33.936 25.913 48.456 ;
     RECT  25.733 51.312 25.955 51.336 ;
     RECT  25.013 27.888 26.129 27.912 ;
     RECT  25.859 53.04 26.129 53.976 ;
     RECT  24.725 32.592 26.197 32.616 ;
     RECT  26.197 32.544 26.198 32.616 ;
     RECT  25.913 33.936 26.269 35.448 ;
     RECT  26.129 53.04 26.284 53.88 ;
     RECT  26.284 53.088 26.339 53.88 ;
     RECT  26.339 53.136 26.435 53.88 ;
     RECT  25.913 36.624 26.521 48.456 ;
     RECT  26.435 53.184 26.531 53.88 ;
     RECT  24.803 31.152 26.953 31.176 ;
     RECT  26.521 36.624 27.205 49.08 ;
     RECT  27.205 36.624 27.277 49.32 ;
     RECT  27.277 36.624 27.389 49.368 ;
     RECT  26.531 53.856 27.529 53.88 ;
     RECT  27.529 53.088 27.541 53.88 ;
     RECT  27.541 52.416 27.629 53.88 ;
     RECT  27.389 36.768 27.641 49.368 ;
     RECT  27.629 52.368 27.713 53.88 ;
     RECT  26.953 31.152 27.745 31.32 ;
     RECT  26.198 32.544 27.745 32.568 ;
     RECT  27.713 52.416 27.779 53.88 ;
     RECT  27.779 52.416 27.821 53.112 ;
     RECT  27.821 53.04 27.875 53.112 ;
     RECT  26.269 33.792 27.889 35.448 ;
     RECT  27.641 36.768 28.609 37.272 ;
     RECT  28.609 36.768 28.681 37.416 ;
     RECT  27.745 31.152 28.693 32.568 ;
     RECT  27.889 33.792 28.753 35.496 ;
     RECT  28.681 36.48 28.753 37.416 ;
     RECT  27.875 53.088 28.897 53.112 ;
     RECT  28.897 53.04 28.933 53.112 ;
     RECT  27.641 38.448 29.005 49.368 ;
     RECT  29.173 51.312 29.185 51.336 ;
     RECT  28.933 52.464 29.221 53.112 ;
     RECT  28.753 33.792 29.257 37.416 ;
     RECT  29.005 38.448 29.257 50.184 ;
     RECT  29.257 33.792 29.269 50.184 ;
     RECT  28.693 31.152 29.408 32.76 ;
     RECT  29.269 33.792 29.408 50.328 ;
     RECT  29.185 51.312 29.408 51.432 ;
     RECT  29.221 52.464 29.408 53.832 ;
     RECT  29.408 2.148 29.512 53.832 ;
     RECT  29.512 2.418 29.704 53.832 ;
     RECT  29.704 33.84 29.981 33.864 ;
     RECT  29.704 35.76 30.089 53.832 ;
     RECT  30.089 50.448 30.179 53.832 ;
     RECT  30.089 35.76 30.197 49.368 ;
     RECT  30.179 52.992 30.377 53.832 ;
     RECT  30.377 53.808 30.707 53.832 ;
     RECT  29.704 31.104 30.949 31.224 ;
     RECT  29.704 32.736 30.956 32.808 ;
     RECT  30.949 31.104 30.989 31.32 ;
     RECT  30.989 31.2 31.025 31.32 ;
     RECT  30.197 36.384 31.093 49.368 ;
     RECT  30.179 50.448 31.093 51.864 ;
     RECT  31.093 36.384 31.205 51.864 ;
     RECT  30.956 32.736 31.285 33.24 ;
     RECT  31.205 36.384 31.313 40.392 ;
     RECT  31.313 36.384 31.421 40.344 ;
     RECT  31.561 53.856 31.645 53.88 ;
     RECT  31.421 36.384 31.705 38.472 ;
     RECT  31.705 36.144 31.777 38.472 ;
     RECT  31.025 31.296 31.885 31.32 ;
     RECT  31.285 32.448 31.885 33.24 ;
     RECT  31.885 31.296 31.925 33.24 ;
     RECT  32.245 34.752 32.281 34.776 ;
     RECT  32.281 34.752 32.353 34.872 ;
     RECT  31.205 41.424 32.389 51.864 ;
     RECT  31.957 52.992 32.389 53.016 ;
     RECT  31.925 31.92 32.461 33.24 ;
     RECT  32.389 41.424 32.483 53.016 ;
     RECT  32.353 34.656 32.573 34.872 ;
     RECT  32.483 41.424 32.609 51.816 ;
     RECT  32.461 31.92 32.821 33.624 ;
     RECT  31.421 39.744 32.821 40.344 ;
     RECT  31.777 36 32.857 38.472 ;
     RECT  32.821 39.504 32.857 40.344 ;
     RECT  32.821 31.92 33.005 34.44 ;
     RECT  32.483 52.896 33.059 53.016 ;
     RECT  32.857 36 33.068 40.344 ;
     RECT  33.068 36 33.077 40.44 ;
     RECT  33.005 33.6 33.113 34.44 ;
     RECT  33.077 36.432 33.253 40.44 ;
     RECT  32.609 41.424 33.253 51.768 ;
     RECT  33.829 34.656 34.045 34.68 ;
     RECT  33.113 33.6 34.261 33.624 ;
     RECT  34.045 34.656 34.261 35.304 ;
     RECT  34.261 33.6 34.369 35.304 ;
     RECT  33.253 36.432 34.369 51.768 ;
     RECT  34.405 53.76 34.549 53.784 ;
     RECT  32.857 30.864 34.808 30.888 ;
     RECT  34.369 33.6 34.808 51.768 ;
     RECT  34.808 2.148 34.837 51.852 ;
     RECT  34.837 2.148 34.912 52.008 ;
     RECT  34.912 2.418 35.104 52.008 ;
     RECT  35.104 30.864 35.165 30.888 ;
     RECT  35.104 35.424 35.165 39.768 ;
     RECT  35.165 36.528 35.201 39.768 ;
     RECT  34.549 53.568 35.218 53.784 ;
     RECT  35.218 53.568 35.219 53.88 ;
     RECT  35.104 40.896 35.309 52.008 ;
     RECT  35.309 40.896 35.381 51.576 ;
     RECT  35.165 35.424 35.417 35.448 ;
     RECT  35.219 53.664 35.497 53.88 ;
     RECT  35.497 53.76 35.669 53.88 ;
     RECT  35.104 33.312 35.705 34.392 ;
     RECT  35.381 40.944 35.741 51.576 ;
     RECT  35.201 36.528 35.921 38.952 ;
     RECT  35.741 41.424 36.037 51.576 ;
     RECT  35.921 38.448 36.173 38.952 ;
     RECT  35.705 33.312 36.281 34.248 ;
     RECT  36.037 50.544 36.317 51.576 ;
     RECT  35.921 36.528 36.529 37.416 ;
     RECT  36.281 34.224 36.569 34.248 ;
     RECT  36.317 50.736 36.641 51.576 ;
     RECT  36.641 50.736 36.929 51.384 ;
     RECT  36.529 35.904 37.213 37.416 ;
     RECT  36.173 38.928 37.213 38.952 ;
     RECT  36.037 41.424 37.217 49.56 ;
     RECT  37.105 34.608 37.285 34.632 ;
     RECT  37.213 35.904 37.285 38.952 ;
     RECT  37.217 41.424 37.433 41.976 ;
     RECT  37.217 43.056 37.433 49.56 ;
     RECT  35.669 53.76 37.501 53.784 ;
     RECT  37.433 43.056 37.541 47.4 ;
     RECT  37.501 53.76 37.577 53.88 ;
     RECT  36.929 51.36 37.609 51.384 ;
     RECT  37.541 44.976 37.685 47.4 ;
     RECT  37.577 53.856 37.763 53.88 ;
     RECT  37.433 41.424 37.933 41.448 ;
     RECT  37.685 44.976 37.937 46.296 ;
     RECT  37.609 51.36 37.996 51.864 ;
     RECT  37.285 34.608 38.005 38.952 ;
     RECT  37.937 45.024 38.045 46.296 ;
     RECT  37.996 51.36 38.081 51.816 ;
     RECT  37.933 40.656 38.153 41.448 ;
     RECT  38.101 51.312 38.188 51.336 ;
     RECT  38.153 40.656 38.197 40.68 ;
     RECT  37.541 43.056 38.225 43.944 ;
     RECT  38.197 40.464 38.243 40.68 ;
     RECT  38.045 45.024 38.369 46.056 ;
     RECT  38.005 34.608 38.513 39.336 ;
     RECT  37.433 48.384 38.513 49.56 ;
     RECT  38.513 34.704 38.549 39.336 ;
     RECT  38.225 43.056 38.549 43.08 ;
     RECT  38.549 34.704 38.765 38.952 ;
     RECT  38.765 36.768 38.801 38.952 ;
     RECT  38.243 40.464 38.801 40.488 ;
     RECT  38.765 34.704 39.089 35.784 ;
     RECT  39.157 52.416 39.241 52.44 ;
     RECT  37.685 47.28 39.697 47.4 ;
     RECT  38.513 48.384 39.697 49.512 ;
     RECT  37.825 33.12 39.841 33.144 ;
     RECT  38.369 45.024 39.877 45.528 ;
     RECT  39.697 47.28 40.069 49.512 ;
     RECT  39.949 50.928 40.069 50.952 ;
     RECT  40.069 47.28 40.093 50.952 ;
     RECT  40.069 53.856 40.093 53.88 ;
     RECT  39.877 44.448 40.129 45.528 ;
     RECT  40.057 51.984 40.129 52.008 ;
     RECT  39.841 33.024 40.165 33.144 ;
     RECT  38.833 31.776 40.208 31.8 ;
     RECT  40.165 33.024 40.208 33.336 ;
     RECT  39.089 34.704 40.208 34.728 ;
     RECT  39.089 35.76 40.208 35.784 ;
     RECT  38.801 36.864 40.208 38.952 ;
     RECT  39.085 40.416 40.208 40.44 ;
     RECT  40.069 41.76 40.208 42.456 ;
     RECT  40.129 44.448 40.208 45.576 ;
     RECT  40.093 46.8 40.208 50.952 ;
     RECT  40.129 51.936 40.208 52.008 ;
     RECT  40.093 53.04 40.259 53.88 ;
     RECT  40.208 2.148 40.312 52.008 ;
     RECT  40.312 2.418 40.501 52.008 ;
     RECT  40.259 53.04 40.501 53.064 ;
     RECT  40.501 2.418 40.504 53.064 ;
     RECT  40.504 33.024 40.529 33.672 ;
     RECT  40.504 41.76 40.643 53.064 ;
     RECT  40.529 33.312 40.745 33.672 ;
     RECT  40.643 44.448 40.745 53.064 ;
     RECT  40.745 50.496 40.817 53.064 ;
     RECT  40.817 51.312 40.931 53.064 ;
     RECT  40.931 51.312 41.027 51.864 ;
     RECT  40.745 44.448 41.105 49.512 ;
     RECT  41.027 51.792 41.357 51.864 ;
     RECT  40.931 52.944 41.425 53.064 ;
     RECT  40.643 41.76 41.501 43.32 ;
     RECT  41.425 52.944 41.509 53.88 ;
     RECT  40.745 33.648 41.537 33.672 ;
     RECT  41.509 52.944 41.537 52.968 ;
     RECT  41.105 44.448 41.573 45.72 ;
     RECT  40.504 35.712 41.605 38.472 ;
     RECT  40.504 40.416 41.605 40.44 ;
     RECT  41.357 51.792 41.609 51.816 ;
     RECT  41.105 46.752 41.645 49.512 ;
     RECT  41.605 40.416 41.713 41.208 ;
     RECT  40.504 31.536 41.785 31.56 ;
     RECT  41.605 34.752 41.789 38.472 ;
     RECT  41.785 31.536 41.825 31.896 ;
     RECT  41.645 46.752 42.041 49.128 ;
     RECT  42.041 47.184 42.113 49.128 ;
     RECT  41.825 31.872 42.181 31.896 ;
     RECT  41.789 35.712 42.221 38.472 ;
     RECT  42.181 31.872 42.227 31.992 ;
     RECT  41.501 42.72 42.227 43.32 ;
     RECT  42.181 50.16 42.265 50.184 ;
     RECT  41.713 40.176 42.293 41.208 ;
     RECT  42.227 43.2 42.517 43.32 ;
     RECT  41.573 44.448 42.517 45.576 ;
     RECT  42.517 43.2 42.577 45.576 ;
     RECT  42.397 51.84 42.577 51.912 ;
     RECT  42.221 38.016 42.617 38.472 ;
     RECT  42.293 41.184 42.725 41.208 ;
     RECT  42.577 51.312 42.755 51.912 ;
     RECT  42.221 35.712 42.833 36.888 ;
     RECT  42.577 43.2 42.833 45.912 ;
     RECT  42.755 51.744 42.865 51.912 ;
     RECT  42.805 49.632 42.892 49.656 ;
     RECT  42.833 44.976 42.905 45.912 ;
     RECT  42.833 36.624 42.941 36.888 ;
     RECT  42.397 33.264 43.049 33.288 ;
     RECT  42.617 38.112 43.153 38.472 ;
     RECT  42.941 36.864 43.157 36.888 ;
     RECT  42.227 31.968 43.189 31.992 ;
     RECT  42.833 43.2 43.193 43.896 ;
     RECT  43.189 31.968 43.229 32.184 ;
     RECT  42.865 51.744 43.381 52.536 ;
     RECT  43.229 32.16 43.405 32.184 ;
     RECT  42.113 47.184 43.441 48.6 ;
     RECT  43.405 32.16 43.445 32.472 ;
     RECT  43.381 51.744 43.541 52.968 ;
     RECT  43.441 47.184 43.549 48.648 ;
     RECT  43.193 43.872 43.553 43.896 ;
     RECT  43.541 51.744 43.625 53.016 ;
     RECT  43.549 47.184 43.693 49.176 ;
     RECT  43.625 51.744 43.697 52.44 ;
     RECT  43.693 46.944 43.729 49.176 ;
     RECT  43.697 51.744 43.729 51.864 ;
     RECT  43.153 38.112 43.801 38.664 ;
     RECT  43.729 51.312 43.841 51.864 ;
     RECT  43.841 51.312 43.877 51.768 ;
     RECT  43.877 51.312 43.907 51.336 ;
     RECT  43.729 46.656 43.981 49.176 ;
     RECT  42.293 40.176 44.021 40.2 ;
     RECT  43.801 43.92 44.197 44.472 ;
     RECT  43.981 45.984 44.197 49.176 ;
     RECT  43.957 53.856 44.273 53.88 ;
     RECT  43.445 32.448 44.732 32.472 ;
     RECT  44.485 35.328 44.773 35.352 ;
     RECT  44.593 36.48 44.773 36.504 ;
     RECT  44.773 35.328 45.025 36.504 ;
     RECT  44.197 43.92 45.053 49.176 ;
     RECT  45.025 34.464 45.169 36.504 ;
     RECT  45.169 34.464 45.308 36.648 ;
     RECT  45.013 52.992 45.317 53.016 ;
     RECT  44.732 31.872 45.565 32.472 ;
     RECT  45.308 34.464 45.601 36.984 ;
     RECT  45.565 31.776 45.608 32.472 ;
     RECT  45.601 33.648 45.608 36.984 ;
     RECT  43.801 38.112 45.608 38.712 ;
     RECT  45.053 43.296 45.608 49.176 ;
     RECT  45.608 2.148 45.712 51.852 ;
     RECT  45.712 2.418 45.904 51.852 ;
     RECT  45.904 36.096 45.965 36.648 ;
     RECT  45.904 51.84 46.061 51.852 ;
     RECT  45.904 44.4 46.109 46.152 ;
     RECT  46.061 51.84 46.145 51.864 ;
     RECT  45.904 47.904 46.253 49.032 ;
     RECT  46.253 47.904 46.289 47.928 ;
     RECT  46.109 45.168 46.325 46.152 ;
     RECT  45.965 36.096 46.505 36.552 ;
     RECT  45.904 34.752 46.541 34.776 ;
     RECT  46.325 45.168 46.793 45.576 ;
     RECT  46.793 45.552 46.829 45.576 ;
     RECT  46.505 36.528 47.333 36.552 ;
     RECT  45.904 31.776 47.513 31.8 ;
     RECT  45.904 33.024 47.513 33.048 ;
     RECT  47.581 34.8 47.725 34.824 ;
     RECT  47.725 34.8 47.873 34.92 ;
     RECT  47.833 33.504 48.197 33.528 ;
     RECT  51.008 2.148 51.112 51.852 ;
     RECT  51.112 2.418 51.304 51.582 ;
     RECT  56.408 2.148 56.512 51.852 ;
     RECT  56.512 2.418 56.704 51.582 ;
     RECT  61.808 2.148 61.912 51.852 ;
     RECT  61.912 2.418 62.104 51.582 ;
     RECT  67.208 2.148 67.312 51.852 ;
     RECT  67.312 2.418 67.504 51.582 ;
     RECT  72.608 2.148 72.712 51.852 ;
     RECT  72.712 2.418 72.904 51.582 ;
     RECT  78.008 2.148 78.112 51.852 ;
     RECT  78.112 2.418 78.304 51.582 ;
     RECT  83.408 2.148 83.512 51.852 ;
     RECT  83.512 2.418 83.704 51.582 ;
    LAYER M5 ;
     RECT  10.464 0.016 13.464 0.085 ;
     RECT  14.496 0.016 17.496 0.085 ;
     RECT  4.032 0.016 4.056 0.131 ;
     RECT  6.144 0.016 6.168 0.131 ;
     RECT  7.2 0.016 7.224 0.131 ;
     RECT  8.256 0.016 8.28 0.131 ;
     RECT  9.312 0.016 9.432 0.131 ;
     RECT  9.408 0.131 9.432 0.179 ;
     RECT  10.464 0.085 17.496 0.517 ;
     RECT  18.528 0.016 18.552 0.517 ;
     RECT  10.464 0.517 18.552 0.611 ;
     RECT  21.792 0.016 21.912 0.611 ;
     RECT  22.944 0.016 22.968 0.611 ;
     RECT  5.088 0.016 5.112 1.763 ;
     RECT  10.944 0.611 18.552 1.763 ;
     RECT  19.584 0.016 19.704 1.763 ;
     RECT  20.736 0.016 20.76 1.763 ;
     RECT  21.888 0.611 21.912 1.763 ;
     RECT  14.688 1.763 18.552 2.137 ;
     RECT  2.4 2.137 2.52 2.151 ;
     RECT  7.8 2.137 7.92 2.151 ;
     RECT  24 2.137 24.12 2.151 ;
     RECT  29.4 2.137 29.52 2.151 ;
     RECT  34.8 2.137 34.92 2.151 ;
     RECT  40.2 2.137 40.32 2.151 ;
     RECT  45.6 2.137 45.72 2.151 ;
     RECT  51 2.137 51.12 2.151 ;
     RECT  56.4 2.137 56.52 2.151 ;
     RECT  61.8 2.137 61.92 2.151 ;
     RECT  67.2 2.137 67.32 2.151 ;
     RECT  72.6 2.137 72.72 2.151 ;
     RECT  78 2.137 78.12 2.151 ;
     RECT  83.4 2.137 83.52 2.151 ;
     RECT  10.944 1.763 13.608 2.339 ;
     RECT  14.688 2.137 18.912 2.339 ;
     RECT  15.072 2.339 18.912 2.915 ;
     RECT  17.472 2.915 18.912 3.397 ;
     RECT  10.944 2.339 11.4 3.443 ;
     RECT  12.48 2.339 13.608 3.443 ;
     RECT  17.472 3.397 20.04 3.443 ;
     RECT  11.04 3.443 11.4 3.491 ;
     RECT  12.672 3.443 13.608 3.877 ;
     RECT  15.072 2.915 16.344 4.019 ;
     RECT  17.472 3.443 17.496 4.019 ;
     RECT  15.12 4.019 16.104 4.259 ;
     RECT  12.672 3.877 13.656 4.595 ;
     RECT  18.6 3.443 20.04 4.691 ;
     RECT  24 2.151 24.312 4.981 ;
     RECT  13.104 4.595 13.656 5.027 ;
     RECT  20.016 4.691 20.04 5.171 ;
     RECT  13.104 5.027 13.608 5.315 ;
     RECT  24 4.981 24.456 5.365 ;
     RECT  23.376 5.365 24.456 5.557 ;
     RECT  25.488 5.173 25.512 5.557 ;
     RECT  21.216 4.597 21.24 5.605 ;
     RECT  11.376 3.491 11.4 6.229 ;
     RECT  4.128 5.029 4.152 6.275 ;
     RECT  10.8 6.229 11.4 6.323 ;
     RECT  7.8 2.151 8.112 6.805 ;
     RECT  13.104 5.315 13.512 6.901 ;
     RECT  15.12 4.259 15.816 6.901 ;
     RECT  18.6 4.691 18.912 7.045 ;
     RECT  20.208 5.941 20.232 7.045 ;
     RECT  13.104 6.901 15.816 7.715 ;
     RECT  18.6 7.045 20.232 7.765 ;
     RECT  21.216 5.605 21.864 7.765 ;
     RECT  13.2 7.715 15.816 8.051 ;
     RECT  17.088 8.245 17.112 8.387 ;
     RECT  18.6 7.765 21.864 8.389 ;
     RECT  23.376 5.557 25.512 8.389 ;
     RECT  7.8 6.805 8.232 8.579 ;
     RECT  15.504 8.051 15.816 8.579 ;
     RECT  9.696 7.957 9.72 8.771 ;
     RECT  10.8 6.323 10.824 8.963 ;
     RECT  18.6 8.389 25.512 9.011 ;
     RECT  18.6 9.011 18.912 9.061 ;
     RECT  15.792 8.579 15.816 9.155 ;
     RECT  20.208 9.011 25.512 9.491 ;
     RECT  20.208 9.491 21.864 9.539 ;
     RECT  13.2 8.051 14.424 10.453 ;
     RECT  17.664 9.061 18.912 10.643 ;
     RECT  20.736 9.539 21.864 10.789 ;
     RECT  12.912 10.453 14.424 10.979 ;
     RECT  20.736 10.789 21.912 11.269 ;
     RECT  20.448 11.269 21.912 11.749 ;
     RECT  15.888 10.597 15.912 12.035 ;
     RECT  20.448 11.749 22.008 13.045 ;
     RECT  23.376 9.491 25.512 13.045 ;
     RECT  13.2 10.979 14.424 14.675 ;
     RECT  0.192 4.021 0.216 27.731 ;
     RECT  40.2 2.151 40.512 31.765 ;
     RECT  45.6 2.151 45.912 31.861 ;
     RECT  42.192 31.861 42.216 31.957 ;
     RECT  42.192 31.957 42.744 32.003 ;
     RECT  29.4 2.151 29.712 32.725 ;
     RECT  31.296 32.437 31.32 32.773 ;
     RECT  31.008 32.773 31.32 32.819 ;
     RECT  39.36 31.765 40.512 33.155 ;
     RECT  31.008 32.819 31.032 33.251 ;
     RECT  42.72 32.003 42.744 33.299 ;
     RECT  34.8 2.151 35.112 33.589 ;
     RECT  18.6 10.643 18.912 34.453 ;
     RECT  20.448 13.045 25.512 34.453 ;
     RECT  33.84 33.589 35.112 34.691 ;
     RECT  37.344 34.597 37.368 35.317 ;
     RECT  37.344 35.317 37.608 35.363 ;
     RECT  41.616 34.741 41.64 35.747 ;
     RECT  17.232 32.581 17.256 35.749 ;
     RECT  18.6 34.453 25.512 35.749 ;
     RECT  17.232 35.749 25.512 35.939 ;
     RECT  34.704 34.691 35.112 35.939 ;
     RECT  17.232 35.939 25.272 35.987 ;
     RECT  18.144 35.987 25.272 36.371 ;
     RECT  28.704 32.725 29.712 36.515 ;
     RECT  37.584 35.363 37.608 36.949 ;
     RECT  18.144 36.371 18.912 37.043 ;
     RECT  40.2 33.155 40.512 37.573 ;
     RECT  40.08 37.573 40.512 38.005 ;
     RECT  10.512 36.901 10.536 38.051 ;
     RECT  37.296 36.949 37.608 38.147 ;
     RECT  44.784 31.861 45.912 38.147 ;
     RECT  11.952 38.005 11.976 38.149 ;
     RECT  13.2 14.675 13.512 38.149 ;
     RECT  29.4 36.515 29.712 38.149 ;
     RECT  34.8 35.939 35.112 38.149 ;
     RECT  37.584 38.147 37.608 38.195 ;
     RECT  45.36 38.147 45.912 38.243 ;
     RECT  29.28 38.149 29.712 38.771 ;
     RECT  34.8 38.149 35.448 38.963 ;
     RECT  11.952 38.149 13.512 39.349 ;
     RECT  11.712 39.349 13.512 39.731 ;
     RECT  11.952 39.731 13.512 39.923 ;
     RECT  14.832 38.485 14.856 39.923 ;
     RECT  29.4 38.771 29.712 40.165 ;
     RECT  33.6 38.773 33.624 40.259 ;
     RECT  12.384 39.923 13.512 40.309 ;
     RECT  2.4 2.151 2.712 40.357 ;
     RECT  38.208 39.301 38.232 40.691 ;
     RECT  12.384 40.309 13.608 40.739 ;
     RECT  28.512 40.165 29.712 41.171 ;
     RECT  20.448 36.371 25.272 41.269 ;
     RECT  12.384 40.739 13.512 41.749 ;
     RECT  12.384 41.749 13.608 41.891 ;
     RECT  20.448 41.269 25.8 41.893 ;
     RECT  15.792 41.845 15.816 41.941 ;
     RECT  3.744 39.013 3.768 41.987 ;
     RECT  13.2 41.891 13.608 41.987 ;
     RECT  15.504 41.941 15.816 42.131 ;
     RECT  15.648 42.131 15.816 42.179 ;
     RECT  29.4 41.171 29.712 42.229 ;
     RECT  20.448 41.893 26.232 42.467 ;
     RECT  33.12 40.405 33.144 42.467 ;
     RECT  40.08 38.005 41.16 42.467 ;
     RECT  15.648 42.179 15.672 42.563 ;
     RECT  42.192 41.173 42.216 43.235 ;
     RECT  13.2 41.987 13.512 43.285 ;
     RECT  45.6 38.243 45.912 43.285 ;
     RECT  30.768 42.661 30.792 43.379 ;
     RECT  28.704 42.229 29.712 43.523 ;
     RECT  5.136 43.381 5.16 43.619 ;
     RECT  29.184 43.523 29.712 44.245 ;
     RECT  34.8 38.963 35.112 44.245 ;
     RECT  2.304 40.357 2.712 44.483 ;
     RECT  45.072 43.285 45.912 44.579 ;
     RECT  29.184 44.245 30.264 44.677 ;
     RECT  34.8 44.245 35.304 44.725 ;
     RECT  36.336 43.285 36.36 44.725 ;
     RECT  32.592 44.341 32.616 44.773 ;
     RECT  28.608 44.677 30.264 44.819 ;
     RECT  2.4 44.483 2.712 44.965 ;
     RECT  42.528 43.765 42.552 44.965 ;
     RECT  27.792 44.821 27.816 45.011 ;
     RECT  12.912 43.285 13.512 45.013 ;
     RECT  40.2 42.467 41.16 45.107 ;
     RECT  5.664 44.437 5.688 45.203 ;
     RECT  28.944 44.819 30.264 45.395 ;
     RECT  7.8 8.579 8.112 45.541 ;
     RECT  29.232 45.395 30.264 45.635 ;
     RECT  20.448 42.467 25.272 45.733 ;
     RECT  12.912 45.013 13.608 45.877 ;
     RECT  7.68 45.541 8.112 46.021 ;
     RECT  12.912 45.877 13.752 46.067 ;
     RECT  32.592 44.773 33 46.117 ;
     RECT  12.912 46.067 13.608 46.501 ;
     RECT  2.4 44.965 2.856 46.547 ;
     RECT  34.08 44.725 36.36 46.645 ;
     RECT  31.728 46.117 33 46.693 ;
     RECT  34.032 46.645 36.36 46.693 ;
     RECT  29.232 45.635 29.832 46.741 ;
     RECT  28.608 46.741 29.832 46.787 ;
     RECT  28.608 46.787 29.712 46.883 ;
     RECT  20.448 45.733 25.848 47.123 ;
     RECT  7.68 46.021 8.232 47.125 ;
     RECT  40.2 45.107 41.064 47.315 ;
     RECT  12.528 46.501 13.608 47.651 ;
     RECT  28.848 46.883 29.712 47.651 ;
     RECT  42.192 44.965 42.552 47.699 ;
     RECT  45.6 44.579 45.912 47.749 ;
     RECT  31.728 46.693 36.36 47.987 ;
     RECT  44.88 47.749 45.912 47.989 ;
     RECT  31.728 47.987 36.312 48.085 ;
     RECT  29.184 47.651 29.712 48.133 ;
     RECT  30.912 48.085 36.312 48.133 ;
     RECT  18.6 37.043 18.912 48.181 ;
     RECT  44.88 47.989 46.008 48.467 ;
     RECT  29.184 48.133 36.312 48.661 ;
     RECT  7.68 47.125 9.144 48.853 ;
     RECT  11.952 48.805 11.976 48.853 ;
     RECT  11.76 48.853 11.976 48.901 ;
     RECT  5.904 48.805 5.928 48.949 ;
     RECT  7.68 48.853 9.24 48.949 ;
     RECT  10.512 45.733 10.536 48.949 ;
     RECT  11.76 48.901 12.168 48.949 ;
     RECT  15.216 48.901 15.24 48.949 ;
     RECT  44.88 48.467 45.912 49.043 ;
     RECT  18.6 48.181 19.08 49.091 ;
     RECT  29.136 48.661 36.312 49.187 ;
     RECT  5.328 48.949 5.928 49.285 ;
     RECT  13.2 47.651 13.608 49.333 ;
     RECT  15.072 48.949 15.24 49.333 ;
     RECT  29.184 49.187 36.312 49.333 ;
     RECT  13.2 49.333 15.24 49.429 ;
     RECT  29.184 49.333 36.696 49.475 ;
     RECT  3.936 49.381 3.96 49.477 ;
     RECT  5.28 49.285 5.928 49.477 ;
     RECT  7.68 48.949 12.168 49.525 ;
     RECT  13.2 49.429 15.288 49.525 ;
     RECT  20.448 47.123 25.272 49.619 ;
     RECT  42.192 47.699 42.216 49.621 ;
     RECT  40.2 47.315 40.512 50.005 ;
     RECT  3.936 49.477 5.928 50.101 ;
     RECT  20.448 49.619 25.224 50.195 ;
     RECT  42.192 49.621 42.84 50.195 ;
     RECT  24 50.195 25.176 50.291 ;
     RECT  3.936 50.101 6.264 50.389 ;
     RECT  7.68 49.525 15.96 50.579 ;
     RECT  29.184 49.475 36.312 50.725 ;
     RECT  3.936 50.389 6.6 50.771 ;
     RECT  40.08 50.005 40.512 50.917 ;
     RECT  20.448 50.195 22.776 51.205 ;
     RECT  24 50.291 24.408 51.205 ;
     RECT  4.56 50.771 6.6 51.301 ;
     RECT  18.6 49.091 18.912 51.301 ;
     RECT  20.448 51.205 24.408 51.301 ;
     RECT  40.08 50.917 40.728 51.301 ;
     RECT  42.816 50.195 42.84 51.301 ;
     RECT  4.56 51.301 6.648 51.347 ;
     RECT  7.68 50.579 15.384 51.347 ;
     RECT  29.184 50.725 36.696 51.347 ;
     RECT  4.704 51.347 6.648 51.397 ;
     RECT  7.68 51.347 9.432 51.397 ;
     RECT  10.752 51.347 15.384 51.443 ;
     RECT  42.72 51.301 42.84 51.733 ;
     RECT  43.872 51.301 43.896 51.733 ;
     RECT  11.232 51.443 15.384 51.781 ;
     RECT  38.112 51.301 38.136 51.781 ;
     RECT  40.08 51.301 41.016 51.781 ;
     RECT  38.016 51.781 38.136 51.829 ;
     RECT  42.72 51.733 43.896 51.829 ;
     RECT  45.6 49.043 45.912 51.829 ;
     RECT  2.4 46.547 2.712 51.849 ;
     RECT  11.232 51.781 15.576 51.849 ;
     RECT  17.376 51.301 18.912 51.849 ;
     RECT  51 2.151 51.312 51.849 ;
     RECT  56.4 2.151 56.712 51.849 ;
     RECT  61.8 2.151 62.112 51.849 ;
     RECT  67.2 2.151 67.512 51.849 ;
     RECT  72.6 2.151 72.912 51.849 ;
     RECT  78 2.151 78.312 51.849 ;
     RECT  83.4 2.151 83.712 51.849 ;
     RECT  2.4 51.849 2.52 51.863 ;
     RECT  4.704 51.397 9.432 51.863 ;
     RECT  11.232 51.849 13.32 51.863 ;
     RECT  17.376 51.849 18.72 51.863 ;
     RECT  45.6 51.829 46.104 51.863 ;
     RECT  51 51.849 51.12 51.863 ;
     RECT  56.4 51.849 56.52 51.863 ;
     RECT  61.8 51.849 61.92 51.863 ;
     RECT  67.2 51.849 67.32 51.863 ;
     RECT  72.6 51.849 72.72 51.863 ;
     RECT  78 51.849 78.12 51.863 ;
     RECT  83.4 51.849 83.52 51.863 ;
     RECT  27.648 52.357 27.672 52.405 ;
     RECT  40.08 51.781 41.4 52.405 ;
     RECT  29.232 51.347 35.64 52.453 ;
     RECT  14.4 51.849 15.576 53.029 ;
     RECT  20.448 51.301 25.944 53.029 ;
     RECT  27.552 52.405 27.672 53.029 ;
     RECT  20.448 53.029 26.232 53.077 ;
     RECT  27.552 53.029 27.864 53.077 ;
     RECT  20.448 53.077 26.328 53.125 ;
     RECT  20.448 53.125 26.424 53.173 ;
     RECT  17.376 51.863 18.504 53.701 ;
     RECT  4.704 51.863 6.84 53.845 ;
     RECT  37.824 51.829 38.136 53.845 ;
     RECT  39.168 52.405 41.4 53.845 ;
     RECT  42.528 51.829 43.896 53.845 ;
     RECT  4.032 53.845 6.84 53.891 ;
     RECT  39.168 53.845 41.496 53.891 ;
     RECT  4.032 53.891 4.056 53.968 ;
     RECT  5.088 53.891 6.84 53.968 ;
     RECT  8.16 51.863 9.432 53.968 ;
     RECT  11.232 51.863 12.504 53.968 ;
     RECT  14.304 53.029 15.576 53.968 ;
     RECT  17.376 53.701 18.648 53.968 ;
     RECT  20.448 53.173 26.52 53.968 ;
     RECT  27.552 53.077 27.96 53.968 ;
     RECT  28.992 52.453 35.64 53.968 ;
     RECT  36.672 51.347 36.696 53.968 ;
     RECT  37.728 53.845 38.136 53.968 ;
     RECT  39.168 53.891 39.192 53.968 ;
     RECT  40.224 53.891 41.496 53.968 ;
     RECT  42.528 53.845 43.992 53.968 ;
     RECT  45.024 52.981 45.048 53.968 ;
     RECT  46.08 51.863 46.104 53.968 ;
  END
END ot_s81_engram_mixq_shctl
END LIBRARY
